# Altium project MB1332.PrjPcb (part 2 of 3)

## Sheet SDcard.SchDoc: SD Card
size A4; Date: Not used; ApprovedBy: Not used; CheckedBy: Not used; Author: Not used; CompanyName: STMicroelectronics; DrawnBy: Not used; Engineer: Not used; Organization: Not used; Address1: Not used; Address2: Not used; Address3: Not used; Address4: Not used; DocumentNumber: Not used; Revision: Not used; SheetNumber: 7; SheetTotal: 17

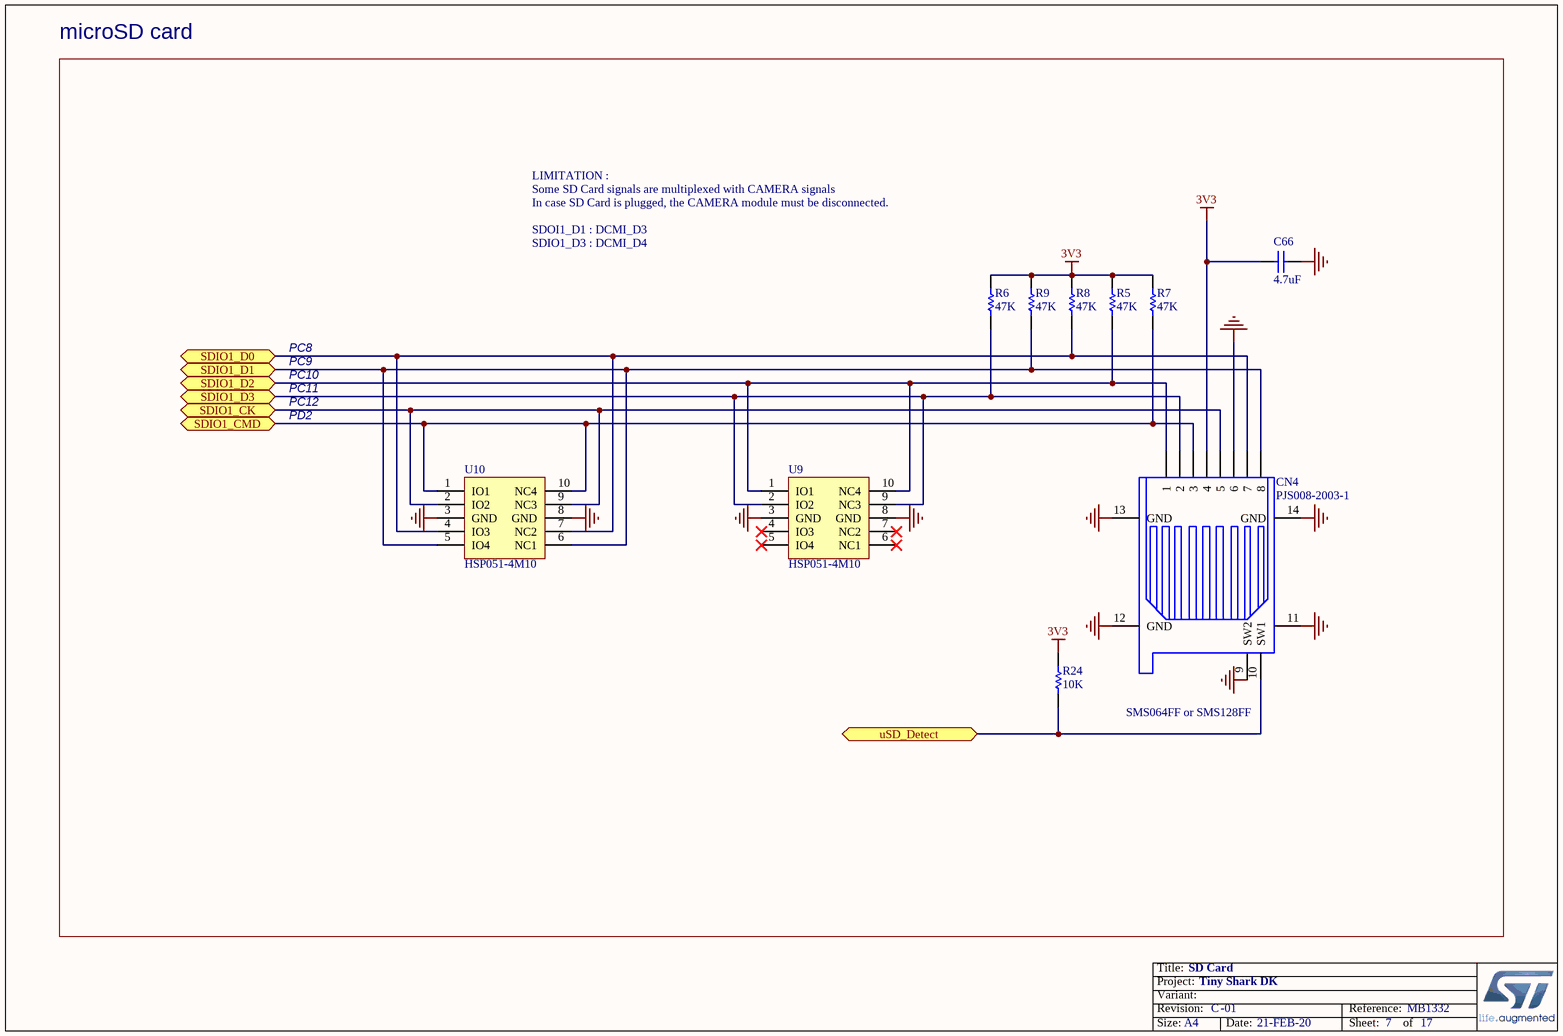
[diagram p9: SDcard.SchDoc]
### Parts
C66  value 4.7uF  [C0603_H0P8]  (hidden comment: Capacitor)
CN4  value PJS008-2003-1  [CON_MICROSD_YAMAICHI_PJS008-2003-1]  (hidden comment: microSD-PJS008-2003)
R5  value 47K  [R0402]  (hidden comment: Resistor)
R6  value 47K  [R0402]  (hidden comment: Resistor)
R7  value 47K  [R0402]  (hidden comment: Resistor)
R8  value 47K  [R0402]  (hidden comment: Resistor)
R9  value 47K  [R0402]  (hidden comment: Resistor)
R24  value 10K  [R0603]  (hidden comment: Resistor)
U9  HSP051-4M10  [ESD_UQFN-10L_2P5X1_P050]
U10  HSP051-4M10  [ESD_UQFN-10L_2P5X1_P050]

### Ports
SDIO1_CK, SDIO1_CMD, SDIO1_D0, SDIO1_D1, SDIO1_D2, SDIO1_D3, uSD_Detect

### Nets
3V3: C66.1 CN4.4 R5.2 R6.2 R7.2 R8.2 R9.2 R24.2
GND: C66.2 CN4.6 CN4.9(SW2) CN4.11(GND) CN4.12(GND) CN4.13(GND) CN4.14(GND) U9.3(GND) U9.8(GND) U10.3(GND) U10.8(GND)
DCMI_D3: CN4.8 R9.1 U10.5(IO4) U10.6(NC1) ; port SDIO1_D1
DCMI_D4: CN4.2 R6.1 U9.2(IO2) U9.9(NC3) ; port SDIO1_D3
SDIO1_CK: CN4.5 U10.2(IO2) U10.9(NC3) ; port SDIO1_CK
SDIO1_CMD: CN4.3 R7.1 U10.1(IO1) U10.10(NC4) ; port SDIO1_CMD
SDIO1_D0: CN4.7 R8.1 U10.4(IO3) U10.7(NC2) ; port SDIO1_D0
SDIO1_D2: CN4.1 R5.1 U9.1(IO1) U9.10(NC4) ; port SDIO1_D2
uSD_Detect: CN4.10(SW1) R24.1 ; port uSD_Detect

Not connected (* = marked no-connect by the designer): U9 4(IO3)* 5(IO4)* 6(NC1)* 7(NC2)*

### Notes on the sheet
- microSD card
- LIMITATION :
  Some SD Card signals are multiplexed with CAMERA signals
  In case SD Card is plugged, the CAMERA module must be disconnected.
  SDOI1_D1 : DCMI_D3
  SDIO1_D3 : DCMI_D4
- PC8
- PC9
- PC10
- PC11
- PD2
- PC12
- SMS064FF or SMS128FF

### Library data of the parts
C66 = MCD-01721: Capacitor, 4.7uF, 10V, X5R, 10%, 0603, T=0.8mm; Manufacturer_Part_Number: CC0603KRX5R6BB475; Manufacturer: YAGEO; Provided_By: SUBCO
CN4 = MCD-00023: MicroSD Card Conn, Reversed-Type, Mnt Push-Push, Positionning holes; Manufacturer: YAMAICHI; Part_Type: Connector; Provided_By: SUBCO
R5-R9 = MCD-00063: Resistor,47K,0402,1%,1/16W; Manufacturer_Part_Number: RC0402FR-0747KL; Manufacturer: YAGEO; Provided_By: SUBCO
R24 = MCD-00220: Resistor,10K,0603,1%,1/10W; Manufacturer_Part_Number: RC0603FR-0710KL; Manufacturer: YAGEO; Provided_By: SUBCO
U9 U10 = MCD-00667: 4-line ESD protection for high speed lines; Part_Type: Diode; Manufacturer: STMICROELECTRONICS; BMS_Part_Number: 9179041; Provided_By: SUBCO with ST control

## Sheet USB_OTG_HS_externalPHY.SchDoc: USB OTG HS with external PHY
size A3; Date: Not used; ApprovedBy: Not used; CheckedBy: Not used; Author: Not used; CompanyName: STMicroelectronics; DrawnBy: Not used; Engineer: Not used; Organization: Not used; Address1: Not used; Address2: Not used; Address3: Not used; Address4: Not used; DocumentNumber: Not used; Revision: Not used; SheetNumber: 4; SheetTotal: 17

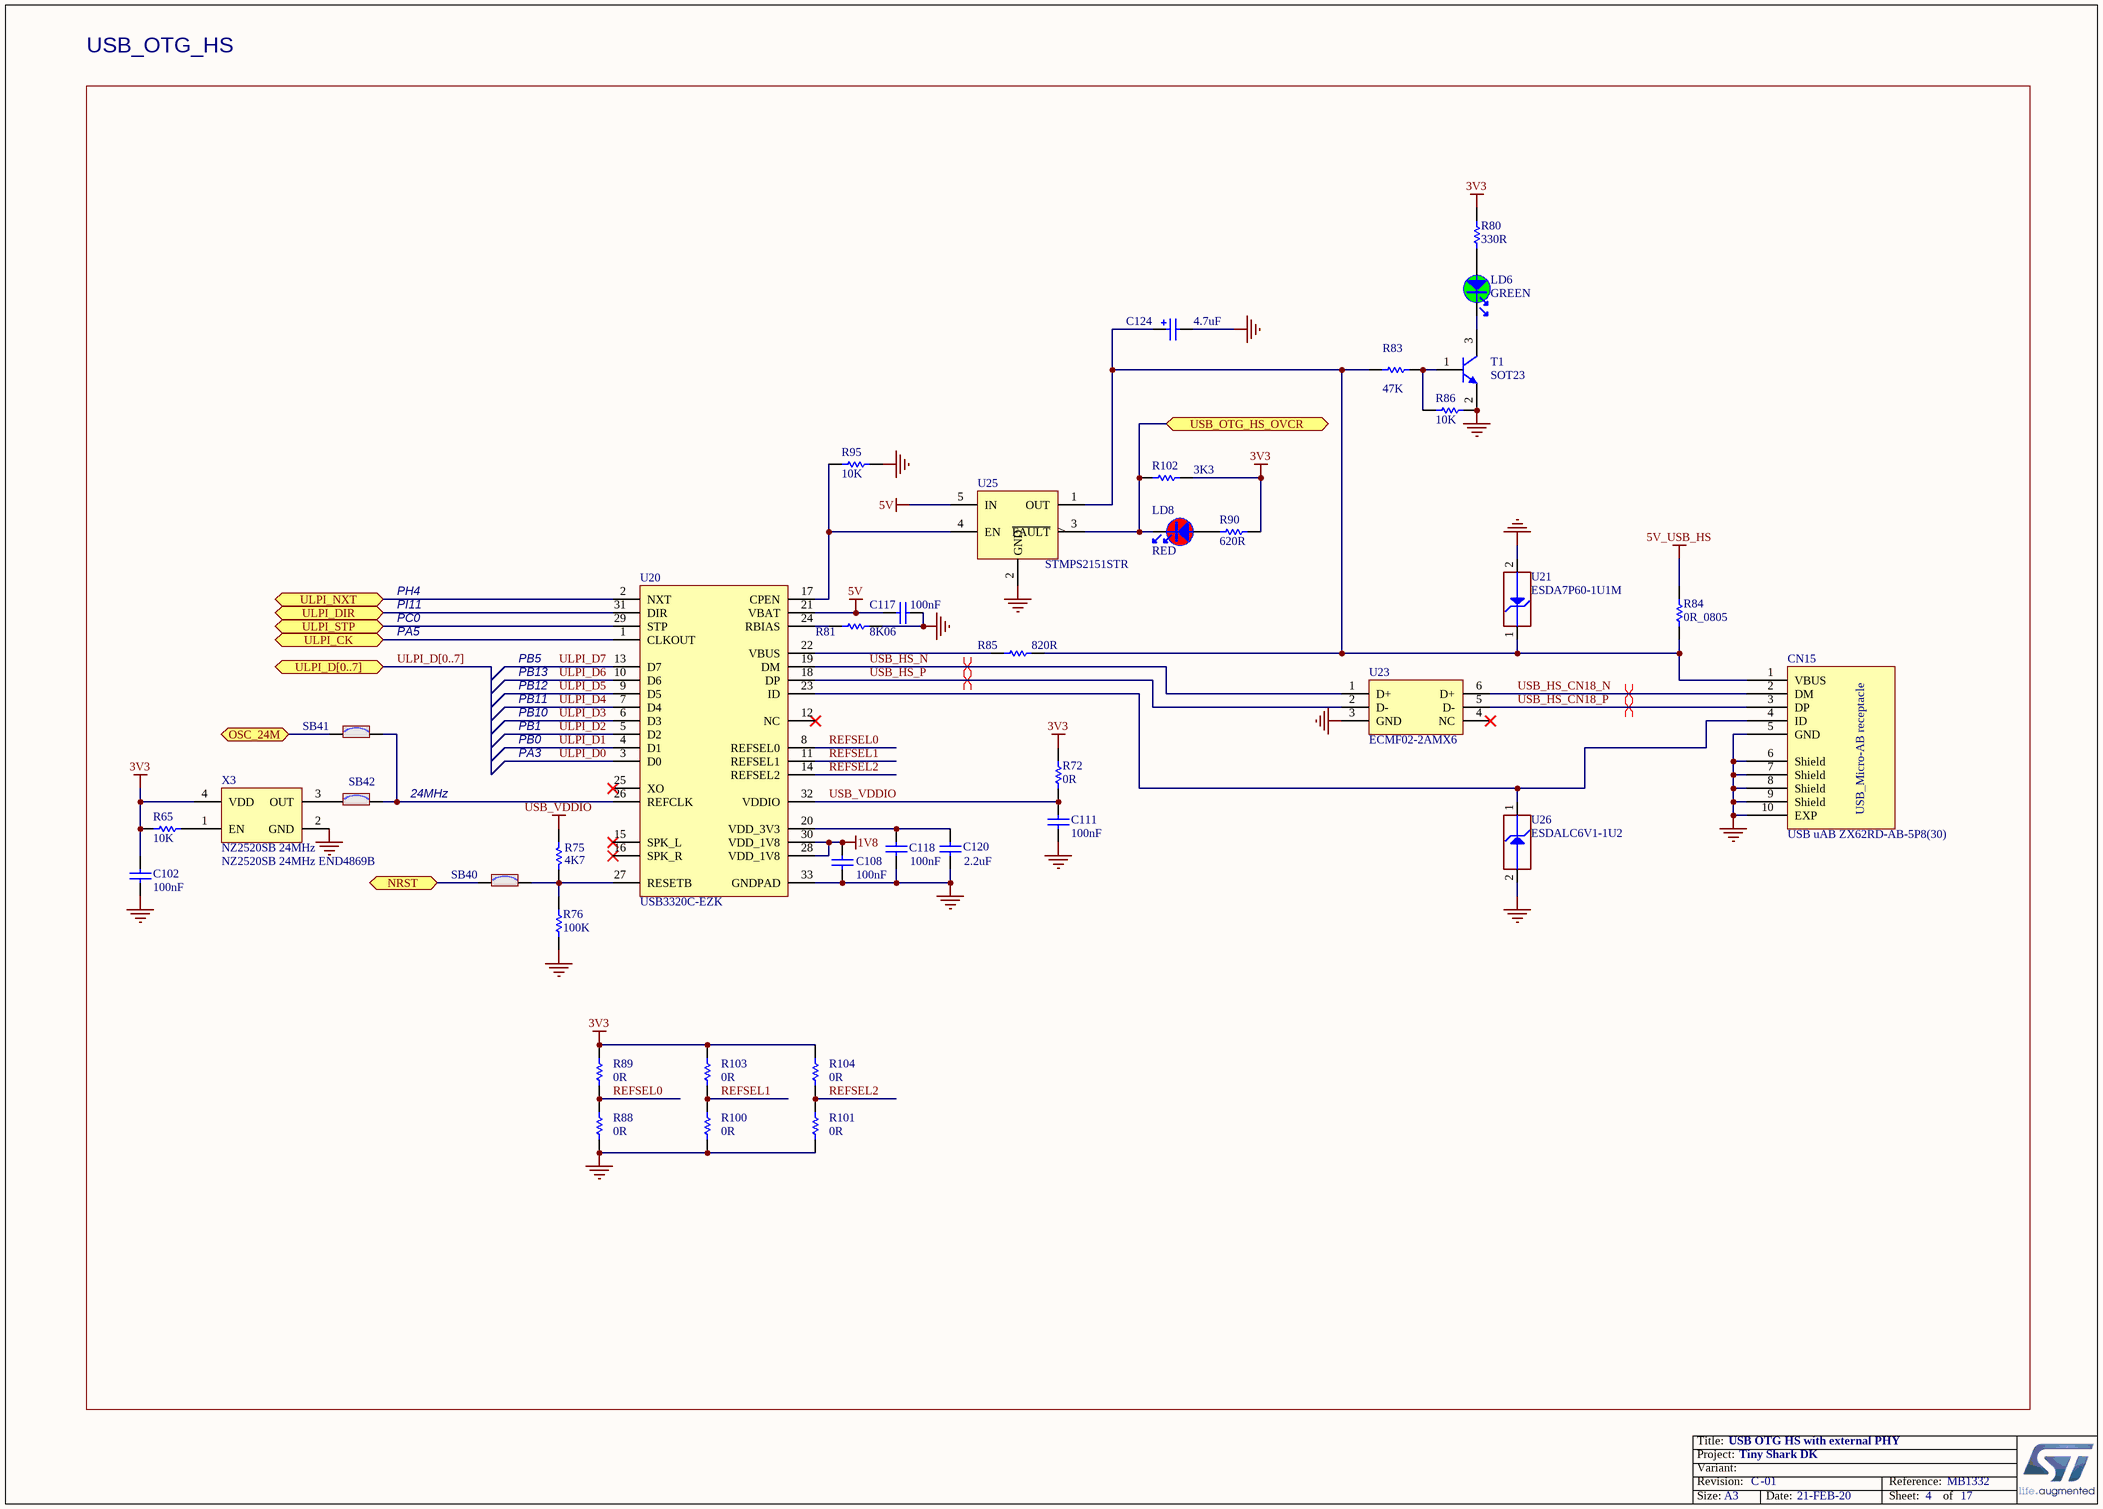
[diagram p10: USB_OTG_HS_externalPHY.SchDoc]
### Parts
C102  value 100nF  [C0402]  (hidden comment: Capacitor)
C108  value 100nF  [C0402]  (hidden comment: Capacitor)
C111  value 100nF  [C0402]  (hidden comment: Capacitor)
C117  value 100nF  [C0402]  (hidden comment: Capacitor)
C118  value 100nF  [C0402]  (hidden comment: Capacitor)
C120  value 2.2uF  [C0603]  (hidden comment: Capacitor)
C124  value 4.7uF  [CPOL_TAJ-A_1206_H180]  (hidden comment: Cap_POL_TANA)
CN15  value USB uAB ZX62RD-AB-5P8(30)  [CON_USBMICROAB_MOLEX_47590-0001_H3]  (hidden comment: USB_uAB_47590.0001)
LD6  value GREEN  [LED_0603_OSRAM_LG-Q396-PS-35_GREEN_1A2K_H0P4]  (hidden comment: LED_green)
LD8  value RED  [LED_0603_VISHAY_VLMS1300-GS08_RED_1A2K_H0P8]  (hidden comment: LED_red)
R65  value 10K  [R0402]  (hidden comment: Resistor)
R72  value 0R  [R0603]  (hidden comment: Resistor)
R75  value 4K7  [R0402]  (hidden comment: Resistor)
R76  value 100K  [R0402]  (hidden comment: Resistor)
R80  value 330R  [R0603]  (hidden comment: Resistor)
R81  value 8K06  [R0603]  (hidden comment: Resistor)
R83  value 47K  [R0402]  (hidden comment: Resistor)
R84  value 0R_0805  [R0805]  (hidden comment: Resistor)
R85  value 820R  [R0603]  (hidden comment: Resistor)
R86  value 10K  [R0402]  (hidden comment: Resistor)
R88  value 0R  [R0603]  (hidden comment: Resistor)
R89  value 0R  [R0603]  (hidden comment: Resistor)
R90  value 620R  [R0603]  (hidden comment: Resistor)
R95  value 10K  [R0402]  (hidden comment: Resistor)
R100  value 0R  [R0603]  (hidden comment: Resistor)
R101  value 0R  [R0603]  (hidden comment: Resistor)
R102  value 3K3  [R0402]  (hidden comment: Resistor)
R103  value 0R  [R0603]  (hidden comment: Resistor)
R104  value 0R  [R0603]  (hidden comment: Resistor)
SB40  SB_ON  [SOLDER-BRIDGE_R0603-0R]  (value not drawn)
SB41  SB_ON  [SOLDER-BRIDGE_R0603-0R]  (value not drawn)
SB42  SB_ON  [SOLDER-BRIDGE_R0603-0R]  (value not drawn)
T1  value SOT23  [NPN_SOT23]  (hidden comment: 9013-SOT23)
U20  USB3320C-EZK  [ICC_QFN32-EPAD_5X5_P050]
U21  value ESDA7P60-1U1M  [ESD_QFN2_1P6X1_P125]  (hidden comment: ESD-TRANSIL)
U23  ECMF02-2AMX6  [ESD_QFN-6L_1P7X1P5_P050]
U25  STMPS2151STR  [MOS_SOT23-5L]
U26  value ESDALC6V1-1U2  [ESD_ST0201]  (hidden comment: ESD-TRANSIL)
X3  value NZ2520SB 24MHz  [OSC_NDK_NZ2520SB_4P]  (hidden comment: OSCILLATOR_4_PINS)

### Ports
NRST, OSC_24M, ULPI_CK, ULPI_D[0..7], ULPI_DIR, ULPI_NXT, ULPI_STP, USB_OTG_HS_OVCR

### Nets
1V8: C108.1 U20.28(VDD_1V8) U20.30(VDD_1V8)
3V3: C102.2 R65.1 R72.1 R80.2 R89.2 R90.2 R102.2 R103.2 R104.2 X3.4(VDD)
5V: C117.1 U20.21(VBAT) U25.5(IN)
5V_USB_HS: R84.2
GND: C102.1 C108.2 C111.2 C117.2 C118.2 C120.1 C124.2 CN15.5(GND) CN15.6(Shield) CN15.7(Shield) CN15.8(Shield) CN15.9(Shield) CN15.10(EXP) R76.1 R81.2 R86.2 R88.1 R95.2 R100.1 R101.1 T1.2(E) U20.33(GNDPAD) U21.2(GND) U23.3(GND) U25.2(GND) U26.2(GND) X3.2(GND)
USB_VDDIO: C111.1 R72.2 R75.2 U20.32(VDDIO)
OSC_24M: SB41.2 ; port OSC_24M
REFSEL0: R88.2 R89.1 U20.8(REFSEL0)
REFSEL1: R100.2 R103.1 U20.11(REFSEL1)
REFSEL2: R101.2 R104.1 U20.14(REFSEL2)
T_NRST: SB40.2 ; port NRST
ULPI_CK: U20.1(CLKOUT) ; port ULPI_CK
ULPI_D0: U20.3(D0)
ULPI_D1: U20.4(D1)
ULPI_D2: U20.5(D2)
ULPI_D3: U20.6(D3)
ULPI_D4: U20.7(D4)
ULPI_D5: U20.9(D5)
ULPI_D6: U20.10(D6)
ULPI_D7: U20.13(D7)
ULPI_DIR: U20.31(DIR) ; port ULPI_DIR
ULPI_NXT: U20.2(NXT) ; port ULPI_NXT
ULPI_STP: U20.29(STP) ; port ULPI_STP
USB_HS_CN18_N: CN15.2(DM) U23.6(D+)
USB_HS_CN18_P: CN15.3(DP) U23.5(D-)
USB_HS_N: U20.19(DM) U23.1(D+)
USB_HS_P: U20.18(DP) U23.2(D-)
USB_OTG_HS_OVCR: LD8.2 R102.1 U25.3(~{FAULT}) ; port USB_OTG_HS_OVCR
NetC118_1: C118.1 C120.2 U20.20(VDD_3V3)
NetC124_1: C124.1 CN15.1(VBUS) R83.1 R84.1 R85.2 U21.1(IO1) U25.1(OUT)
NetCN15_4: CN15.4(ID) U20.23(ID) U26.1(IO1)
NetLD6_1: LD6.1 R80.1
NetLD6_2: LD6.2 T1.3(C)
NetLD8_1: LD8.1 R90.1
NetR65_2: R65.2 X3.1(EN)
NetR75_1: R75.1 R76.2 SB40.1 U20.27(RESETB)
NetR81_1: R81.1 U20.24(RBIAS)
NetR83_2: R83.2 R86.1 T1.1(B)
NetR85_1: R85.1 U20.22(VBUS)
NetR95_1: R95.1 U20.17(CPEN) U25.4(EN)
NetSB41_1: SB41.1 SB42.1 U20.26(REFCLK)
NetSB42_2: SB42.2 X3.3(OUT)

Not connected (* = marked no-connect by the designer): U20 12(NC)* 15(SPK_L)* 16(SPK_R)* 25(XO)*; U23 4(NC)*

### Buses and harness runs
bus ULPI_D[0..7] = port ULPI_D[0..7]

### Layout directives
differential pair: USB_HS_CN18_N, USB_HS_CN18_P, USB_HS_N, USB_HS_P

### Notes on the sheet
- USB_OTG_HS
- PH4
- PI11
- PC0
- PA5
- PB10
- PB11
- PB12
- PB13
- PB5
- PA3
- PB0
- PB1
- (near SB42) 24MHz
- (near X3) NZ2520SB 24MHz END4869B

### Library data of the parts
C102 C108 C111 C117 C118 = MCD-00006: Capacitor, MLCC, 100nF, 16V, X7R, 10%, 0402, T=0.5mm; Manufacturer_Part_Number: CC0402KRX7R7BB104; Manufacturer: YAGEO; Alternate_Manufacturer_Part_Number: GCM155R71C104KA55D; Alternate_Manufacturer: MURATA; Provided_By: SUBCO
C120 = MCD-00012: Capacitor, MLCC, 2.2uF, 10V, X5R, 10%, 0603, T=0,8mm; Manufacturer_Part_Number: CC0603KRX5R6BB225; Manufacturer: YAGEO; Alternate_Manufacturer_Part_Number: C0603C225K8PACTU; Alternate_Manufacturer: KEMET; Provided_By: SUBCO
C124 = MCD-00007: Capacitor, Tantalum, 4.7uF, 16V, 10%, TypeA; Manufacturer_Part_Number: TAJA475K016R; Manufacturer: AVX; Provided_By: SUBCO
CN15 = MCD-00661: USB-MICRO-AB Receptacle, RA, SMT + DIP, Standard, Top Mount, USB certified (symbol & footprint compatible with MCD-00022); Part_Type: Connector; Manufacturer_Part_Number: ZX62RD-AB-5P8(30); Manufacturer: HIROSE; Provided_By: SUBCO
LD6 = MCD-00588: LED Green, 0603 SMD, Forward Voltage Typ=2V, Max=2.5V; Part_Type: Display; Manufacturer_Part_Number: LG Q396-PS-35; Manufacturer: OSRAM OPTO SEMICONDUCTORS; Alternate_Manufacturer_Part_Number: VLMTG1300-GS08; Alternate_Manufacturer: VISHAY SEMICONDUCTOR OPTO DIVISION; Provided_By: SUBCO
LD8 = MCD-00587: LED Red, 0603 SMD, 2V Forward Voltage; Manufacturer_Part_Number: VLMS1300-GS08; Manufacturer: VISHAY; Alternate_Manufacturer_Part_Number: LS Q976-NR-1; Alternate_Manufacturer: OSRAM OPTO SEMICONDUCTORS; Part_Type: Display; Provided_By: SUBCO
R65 R86 R95 = MCD-00053: Resistor,10K,0402,1%,1/16W; Manufacturer_Part_Number: RC0402FR-0710KL; Manufacturer: YAGEO; Provided_By: SUBCO
R72 R88 R89 R100 R101 R103 R104 = MCD-00056: Resistor,0R,0603,5%,1/10W; Manufacturer_Part_Number: RC0603JR-070RL; Manufacturer: YAGEO; Provided_By: SUBCO
R75 = MCD-00065: Resistor,4K7,0402,1%,1/16W; Manufacturer_Part_Number: RC0402FR-074K7L; Manufacturer: YAGEO; Alternate_Manufacturer_Part_Number: RT0402FRE074K7L; Provided_By: SUBCO
R76 = MCD-00059: Resistor,100K,0402,1%,1/16W; Manufacturer_Part_Number: RC0402FR-07100KL; Manufacturer: YAGEO; Alternate_Manufacturer_Part_Number: RT0402FRE07100KL; Provided_By: SUBCO
R80 = MCD-00197: Resistor,330R,0603,1%,1/10W; Manufacturer_Part_Number: RC0603FR-07330RL; Manufacturer: YAGEO; BMS_Part_Number: 9129729; Provided_By: SUBCO
R81 = MCD-00570: Resistor,8K06,0603,1%,1/10W; Manufacturer_Part_Number: RC0603FR-078K06L; Manufacturer: YAGEO; Provided_By: SUBCO
R83 = MCD-00063: as R5 on sheet SDcard
R84 = MCD-00179: Resistor,0R,0805,5%; Manufacturer_Part_Number: RC0805JR-070RL; Manufacturer: YAGEO; Provided_By: SUBCO
R85 = MCD-00528: Resistor,820R,0603,1%,1/10W; Manufacturer_Part_Number: RC0603FR-07820RL; Manufacturer: YAGEO; BMS_Part_Number: 9129759; Provided_By: SUBCO
R90 = MCD-00500: Resistor,620R,0603,1%,1/10W; Manufacturer_Part_Number: RC0603FR-07620RL; Manufacturer: YAGEO; Provided_By: SUBCO
R102 = MCD-00184: Resistor,3K3,0402,1%,1/16W; Manufacturer_Part_Number: RC0402FR-073K3L; Manufacturer: YAGEO; Provided_By: SUBCO
SB40-SB42 = MCD-00071: Solder Bridge ON; Part_Type: Mechanical; Manufacturer_Part_Number: RC0603JR-070RL; Manufacturer: YAGEO; Provided_By: SUBCO
T1 = MCD-00073: NPN Bipolar Transistor; Manufacturer_Part_Number: BSR14; Manufacturer: ON SEMICONDUCTOR; Part_Type: IC; Alternate_Manufacturer_Part_Number: MMBT2222ALT1G / MMBT2222ALT3G; Provided_By: SUBCO
U20 = MCD-00569: USB3320C,  Hi-Speed USB Host, Device or OTG PHY with ULPI Low Pin Interface; Manufacturer_Part_Number: USB3320C-EZK-TR; Manufacturer: MICROCHIP; Part_Type: IC; Provided_By: SUBCO
U21 = MCD-00251: High power transient voltage suppressor, 7V breakdown; Part_Type: Diode; Manufacturer: STMICROELECTRONICS; BMS_Part_Number: 9179042; Provided_By: SUBCO with ST control
U23 = MCD-00649: Common mode filter with ESD protection for USB 2.0 interface; Part_Type: Diode; Manufacturer: STMICROELECTRONICS; BMS_Part_Number: 9151138; Provided_By: SUBCO with ST control
U25 = MCD-00159: 500mA, Enhanced single channel power switches with active high enable pin; Manufacturer: STMICROELECTRONICS; Part_Type: IC; Alternate_Manufacturer_Part_Number: TPS2051C; Alternate_Manufacturer: TEXAS INSTRUMENTS; BMS_Part_Number: 9159009; Provided_By: SUBCO with ST control
U26 = MCD-00170: ESD protection 6V1; Part_Type: Diode; Manufacturer: STMICROELECTRONICS; BMS_Part_Number: 9151132; Provided_By: SUBCO with ST control
X3 = MCD-01014: Oscillator 24Mhz, +-50ppm, Vcc:3.3V typ, square wave: [0.1Vcc;0.9Vcc], Enable pin; Part_Type: Crystal_Osc; Manufacturer_Part_Number: NZ2520SB 24MHz END4869A; Manufacturer: NDK; Alternate_Manufacturer_Part_Number: AVX Corp/Kyocera Corp; Alternate_Manufacturer: KC2520B24.0000C10E00; BMS_Part_Number: 9157032; Provided_By: SUBCO

## Sheet MCU.SchDoc: MCU STM32H7B3LIH6QU
size A3; Date: Not used; ApprovedBy: Not used; CheckedBy: Not used; Author: Not used; CompanyName: STMicroelectronics; DrawnBy: Not used; Engineer: Not used; Organization: Not used; Address1: Not used; Address2: Not used; Address3: Not used; Address4: Not used; DocumentNumber: Not used; Revision: Not used; SheetNumber: 3; SheetTotal: 17

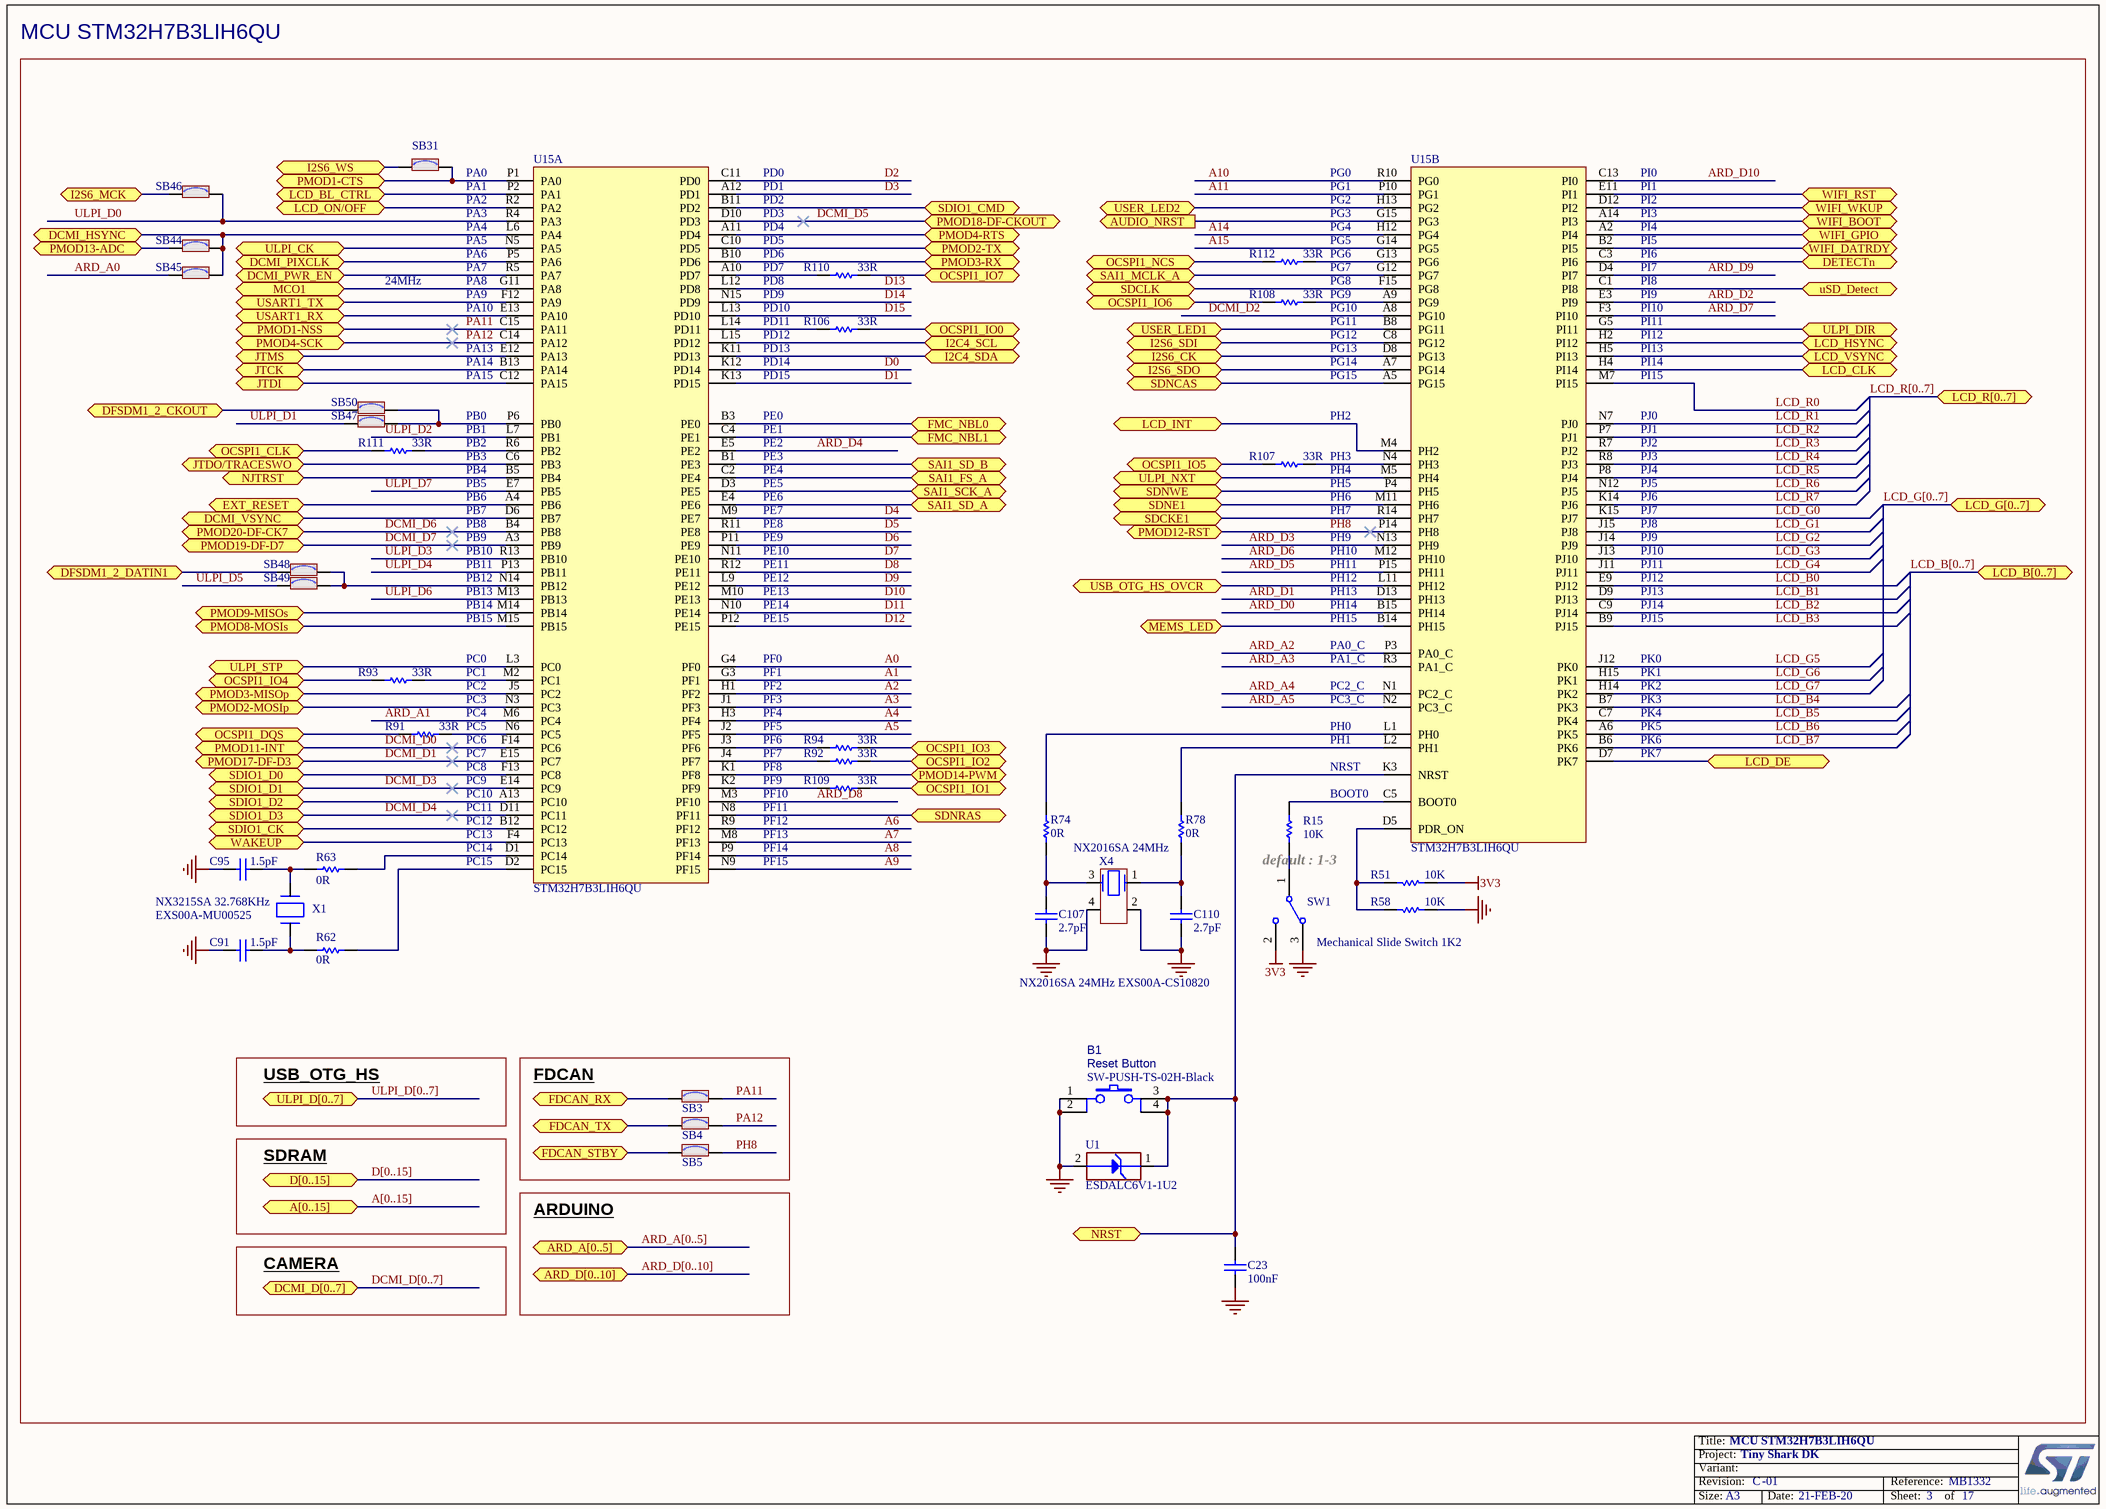
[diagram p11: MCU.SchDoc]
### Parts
B1  SW-PUSH-TS-02H-Black  [SWI_JIUBABA_C-TS-02H-2-5-K-V-T_R_BLACK]
C23  value 100nF  [C0402]  (hidden comment: Capacitor)
C91  value 1.5pF  [C0402]  (hidden comment: Capacitor)
C95  value 1.5pF  [C0402]  (hidden comment: Capacitor)
C107  value 2.7pF  [C0402]  (hidden comment: Capacitor)
C110  value 2.7pF  [C0402]  (hidden comment: Capacitor)
R15  value 10K  [R0402]  (hidden comment: Resistor)
R51  value 10K  [R0402]  (hidden comment: Resistor)
R58  value 10K  [R0402]  (hidden comment: Resistor)
R62  value 0R  [R0402]  (hidden comment: Resistor)
R63  value 0R  [R0402]  (hidden comment: Resistor)
R74  value 0R  [R0402]  (hidden comment: Resistor)
R78  value 0R  [R0402]  (hidden comment: Resistor)
R91  value 33R  [R0402]  (hidden comment: Resistor)
R92  value 33R  [R0402]  (hidden comment: Resistor)
R93  value 33R  [R0402]  (hidden comment: Resistor)
R94  value 33R  [R0402]  (hidden comment: Resistor)
R106  value 33R  [R0402]  (hidden comment: Resistor)
R107  value 33R  [R0402]  (hidden comment: Resistor)
R108  value 33R  [R0402]  (hidden comment: Resistor)
R109  value 33R  [R0402]  (hidden comment: Resistor)
R110  value 33R  [R0402]  (hidden comment: Resistor)
R111  value 33R  [R0402]  (hidden comment: Resistor)
R112  value 33R  [R0402]  (hidden comment: Resistor)
SB3  SB_ON  [SOLDER-BRIDGE_R0603-0R]  (value not drawn)
SB4  SB_ON  [SOLDER-BRIDGE_R0603-0R]  (value not drawn)
SB5  SB_ON  [SOLDER-BRIDGE_R0603-0R]  (value not drawn)
SB31  SB_ON  [SOLDER-BRIDGE_R0603-0R]  (value not drawn)
SB44  SB_ON  [SOLDER-BRIDGE_R0603-0R]  (value not drawn)
SB45  SB_ON  [SOLDER-BRIDGE_R0603-0R]  (value not drawn)
SB46  SB_ON  [SOLDER-BRIDGE_R0603-0R]  (value not drawn)
SB47  SB_ON  [SOLDER-BRIDGE_R0603-0R]  (value not drawn)
SB48  SB_ON  [SOLDER-BRIDGE_R0603-0R]  (value not drawn)
SB49  SB_ON  [SOLDER-BRIDGE_R0603-0R]  (value not drawn)
SB50  SB_ON  [SOLDER-BRIDGE_R0603-0R]  (value not drawn)
SW1  value Mechanical Slide Switch 1K2  [SWI_EAO_09-03290-01_EXTENDED_STRAIGHT_BLACK]  (hidden comment: SW_MECA_1K2)
U1  value ESDALC6V1-1U2  [ESD_ST0201]  (hidden comment: ESD-TRANSIL)
U15  value STM32H7B3LIH6QU  [ICC_TFBGA225_13X13_STM32H7B3NIH6Q_P080]  (hidden comment: STM32H7B3NIH6Q)  (parts A,B of 3)
X1  value NX3215SA 32.768KHz  [CRY_NX3215SA_2P]  (hidden comment: XTAL_2_PINS)
X4  value NX2016SA 24MHz  Manufacturer_Part_Number: NX2016SA 24MHz EXS00A-CS10820  [CRY_NX2016SA_4P]  (hidden comment: XTAL_4_PINS)

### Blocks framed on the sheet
FDCAN: SB3-SB5

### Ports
A[0..15], ARD_A[0..5], ARD_D[0..10], AUDIO_NRST (out), D[0..15], DCMI_D[0..7], DCMI_HSYNC, DCMI_PIXCLK, DCMI_PWR_EN, DCMI_VSYNC, DETECTn, DFSDM1_2_CKOUT, DFSDM1_2_DATIN1, EXT_RESET, FDCAN_RX, FDCAN_STBY, FDCAN_TX, FMC_NBL0, FMC_NBL1, I2C4_SCL, I2C4_SDA, I2S6_CK, I2S6_MCK (bidir), I2S6_SDI, I2S6_SDO, I2S6_WS, JTCK, JTDI, JTDO/TRACESWO, JTMS, LCD_B[0..7], LCD_BL_CTRL, LCD_CLK, LCD_DE, LCD_G[0..7], LCD_HSYNC, LCD_INT, LCD_ON/OFF, LCD_R[0..7], LCD_VSYNC, MCO1, MEMS_LED, NJTRST, NRST, OCSPI1_CLK, OCSPI1_DQS, OCSPI1_IO0, OCSPI1_IO1, OCSPI1_IO2, OCSPI1_IO3, OCSPI1_IO4, OCSPI1_IO5, OCSPI1_IO6, OCSPI1_IO7, OCSPI1_NCS, PMOD1-CTS, PMOD1-NSS, PMOD2-MOSIp, PMOD2-TX, PMOD3-MISOp, PMOD3-RX, PMOD4-RTS, PMOD4-SCK, PMOD8-MOSIs, PMOD9-MISOs, PMOD11-INT, PMOD12-RST, PMOD13-ADC, PMOD14-PWM, PMOD17-DF-D3, PMOD18-DF-CKOUT, PMOD19-DF-D7, PMOD20-DF-CK7, SAI1_FS_A, SAI1_MCLK_A, SAI1_SCK_A, SAI1_SD_A, SAI1_SD_B, SDCKE1, SDCLK, SDIO1_CK, SDIO1_CMD, SDIO1_D0, SDIO1_D1, SDIO1_D2, SDIO1_D3, SDNCAS, SDNE1, SDNRAS, SDNWE, ULPI_CK, ULPI_D[0..7], ULPI_DIR, ULPI_NXT, ULPI_STP, USART1_RX, USART1_TX, USB_OTG_HS_OVCR, uSD_Detect, USER_LED1, USER_LED2, WAKEUP, WIFI_BOOT, WIFI_DATRDY, WIFI_GPIO, WIFI_RST, WIFI_WKUP

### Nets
3V3: R51.1 SW1.2
GND: B1.1 B1.2 C23.1 C91.1 C95.1 C107.1 C110.1 R58.1 SW1.3 U1.2(GND) X4.2 X4.4
2_CTS: SB31.1 U15.P1(PA0) ; port PMOD1-CTS
2_RTS: U15.A11(PD4) ; port PMOD4-RTS
2_RX: U15.B10(PD6) ; port PMOD3-RX
2_TX: U15.C10(PD5) ; port PMOD2-TX
A0: U15.G4(PF0)
A1: U15.G3(PF1)
A2: U15.H1(PF2)
A3: U15.J1(PF3)
A4: U15.H3(PF4)
A5: U15.J2(PF5)
A6: U15.R9(PF12)
A7: U15.M8(PF13)
A8: U15.P9(PF14)
A9: U15.N9(PF15)
A10: U15.R10(PG0)
A11: U15.P10(PG1)
A14: U15.H12(PG4)
A15: U15.G14(PG5)
ARD_A0: SB45.2
ARD_A1: U15.M6(PC4)
ARD_A2: U15.P3(PA0_C)
ARD_A3: U15.R3(PA1_C)
ARD_A4: U15.N1(PC2_C)
ARD_A5: U15.N2(PC3_C)
ARD_D0: U15.B15(PH14)
ARD_D1: U15.D13(PH13)
ARD_D2: U15.E3(PI9)
ARD_D3: U15.N13(PH9)
ARD_D4: U15.E5(PE2)
ARD_D5: U15.P15(PH11)
ARD_D6: U15.M12(PH10)
ARD_D7: U15.F3(PI10)
ARD_D8: U15.M3(PF10)
ARD_D9: U15.D4(PI7)
ARD_D10: U15.C13(PI0)
AUDIO_NRST: U15.G15(PG3) ; port AUDIO_NRST
CKOUT: SB50.2 ; port DFSDM1_2_CKOUT
D0: U15.K12(PD14)
D1: U15.K13(PD15)
D2: U15.C11(PD0)
D3: U15.A12(PD1)
D4: U15.M9(PE7)
D5: U15.R11(PE8)
D6: U15.P11(PE9)
D7: U15.N11(PE10)
D8: U15.R12(PE11)
D9: U15.L9(PE12)
D10: U15.M10(PE13)
D11: U15.N10(PE14)
D12: U15.P12(PE15)
D13: U15.L12(PD8)
D14: U15.N15(PD9)
D15: U15.L13(PD10)
DCMI_D0: U15.F14(PC6) ; port PMOD11-INT
DCMI_D1: U15.E15(PC7) ; port PMOD17-DF-D3
DCMI_D2: U15.A8(PG10)
DCMI_D3: U15.E14(PC9) ; port SDIO1_D1
DCMI_D4: U15.D11(PC11) ; port SDIO1_D3
DCMI_D5: U15.D10(PD3) ; port PMOD18-DF-CKOUT
DCMI_D6: U15.B4(PB8) ; port PMOD20-DF-CK7
DCMI_D7: U15.A3(PB9) ; port PMOD19-DF-D7
DCMI_HSYNC: SB44.1 SB45.1 U15.L6(PA4) ; port DCMI_HSYNC
DCMI_PIXCLK: U15.P5(PA6) ; port DCMI_PIXCLK
DCMI_PWR_EN: U15.R5(PA7) ; port DCMI_PWR_EN
DCMI_VSYNC: U15.D6(PB7) ; port DCMI_VSYNC
DETECTn: U15.C3(PI6) ; port DETECTn
DFSDM1_2_DATIN1: SB48.2 ; port DFSDM1_2_DATIN1
EXT_RESET: U15.A4(PB6) ; port EXT_RESET
FDCAN_RX: SB3.1 ; port FDCAN_RX
FDCAN_STBY: SB5.1 ; port FDCAN_STBY
FDCAN_TX: SB4.1 ; port FDCAN_TX
FMC_NBL0: U15.B3(PE0) ; port FMC_NBL0
FMC_NBL1: U15.C4(PE1) ; port FMC_NBL1
I2C4_SCL: U15.L15(PD12) ; port I2C4_SCL
I2C4_SDA: U15.K11(PD13) ; port I2C4_SDA
I2S6_CK: U15.D8(PG13) ; port I2S6_CK
I2S6_MCK: SB46.2 ; port I2S6_MCK
I2S6_SDI: U15.C8(PG12) ; port I2S6_SDI
I2S6_SDO: U15.A7(PG14) ; port I2S6_SDO
I2S6_WS: SB31.2 ; port I2S6_WS
JTDI: U15.C12(PA15) ; port JTDI
LCD_B0: U15.E9(PJ12)
LCD_B1: U15.D9(PJ13)
LCD_B2: U15.C9(PJ14)
LCD_B3: U15.B9(PJ15)
LCD_B4: U15.B7(PK3)
LCD_B5: U15.C7(PK4)
LCD_B6: U15.A6(PK5)
LCD_B7: U15.B6(PK6)
LCD_BL_CTRL: U15.P2(PA1) ; port LCD_BL_CTRL
LCD_CLK: U15.H4(PI14) ; port LCD_CLK
LCD_DE: U15.D7(PK7) ; port LCD_DE
LCD_G0: U15.K15(PJ7)
LCD_G1: U15.J15(PJ8)
LCD_G2: U15.J14(PJ9)
LCD_G3: U15.J13(PJ10)
LCD_G4: U15.J11(PJ11)
LCD_G5: U15.J12(PK0)
LCD_G6: U15.H15(PK1)
LCD_G7: U15.H14(PK2)
LCD_HSYNC: U15.H2(PI12) ; port LCD_HSYNC
LCD_INT: U15.M4(PH2) ; port LCD_INT
LCD_ON/OFF: U15.R2(PA2) ; port LCD_ON/OFF
LCD_R0: U15.M7(PI15)
LCD_R1: U15.N7(PJ0)
LCD_R2: U15.P7(PJ1)
LCD_R3: U15.R7(PJ2)
LCD_R4: U15.R8(PJ3)
LCD_R5: U15.P8(PJ4)
LCD_R6: U15.N12(PJ5)
LCD_R7: U15.K14(PJ6)
LCD_VSYNC: U15.H5(PI13) ; port LCD_VSYNC
MCO1: U15.G11(PA8) ; port MCO1
MEMS_LED: U15.B14(PH15) ; port MEMS_LED
MISO: U15.J5(PC2) ; port PMOD3-MISOp
MOSI: U15.N3(PC3) ; port PMOD2-MOSIp
NJTRST: U15.B5(PB4) ; port NJTRST
OCSPI1_CLK: R111.1 ; port OCSPI1_CLK
OCSPI1_DQS: R91.1 ; port OCSPI1_DQS
OCSPI1_IO0: R106.2 ; port OCSPI1_IO0
OCSPI1_IO1: R109.2 ; port OCSPI1_IO1
OCSPI1_IO2: R92.2 ; port OCSPI1_IO2
OCSPI1_IO3: R94.2 ; port OCSPI1_IO3
OCSPI1_IO4: R93.1 ; port OCSPI1_IO4
OCSPI1_IO5: R107.1 ; port OCSPI1_IO5
OCSPI1_IO6: R108.1 ; port OCSPI1_IO6
OCSPI1_IO7: R110.2 ; port OCSPI1_IO7
OCSPI1_NCS: R112.1 ; port OCSPI1_NCS
PA11: SB3.2 U15.C15(PA11) ; port PMOD1-NSS  [project net nSS]
PA12: SB4.2 U15.C14(PA12) ; port PMOD4-SCK
PH8: SB5.2 U15.P14(PH8) ; port PMOD12-RST
PMOD8-MOSIs: U15.M15(PB15) ; port PMOD8-MOSIs
PMOD9: U15.M14(PB14) ; port PMOD9-MISOs
PMOD13-ADC: SB44.2 ; port PMOD13-ADC
PMOD14-PWM: U15.K1(PF8) ; port PMOD14-PWM
SAI1_FS_A: U15.C2(PE4) ; port SAI1_FS_A
SAI1_MCLK_A: U15.G12(PG7) ; port SAI1_MCLK_A
SAI1_SCK_A: U15.D3(PE5) ; port SAI1_SCK_A
SAI1_SD_A: U15.E4(PE6) ; port SAI1_SD_A
SAI1_SD_B: U15.B1(PE3) ; port SAI1_SD_B
SDCKE1: U15.R14(PH7) ; port SDCKE1
SDCLK: U15.F15(PG8) ; port SDCLK
SDIO1_CK: U15.B12(PC12) ; port SDIO1_CK
SDIO1_CMD: U15.B11(PD2) ; port SDIO1_CMD
SDIO1_D0: U15.F13(PC8) ; port SDIO1_D0
SDIO1_D2: U15.A13(PC10) ; port SDIO1_D2
SDNCAS: U15.A5(PG15) ; port SDNCAS
SDNE1: U15.M11(PH6) ; port SDNE1
SDNRAS: U15.N8(PF11) ; port SDNRAS
SDNWE: U15.P4(PH5) ; port SDNWE
T_NRST: B1.3 B1.4 C23.2 U1.1(IO1) U15.K3(NRST) ; port NRST
T_SWCLK: U15.B13(PA14) ; port JTCK
T_SWDIO: U15.E12(PA13) ; port JTMS
T_SWO: U15.C6(PB3) ; port JTDO/TRACESWO
ULPI_CK: U15.N5(PA5) ; port ULPI_CK
ULPI_D0: SB46.1 U15.R4(PA3)
ULPI_D1: SB47.2
ULPI_D2: U15.L7(PB1)
ULPI_D3: U15.R13(PB10)
ULPI_D4: U15.P13(PB11)
ULPI_D5: SB49.2
ULPI_D6: U15.M13(PB13)
ULPI_D7: U15.E7(PB5)
ULPI_DIR: U15.G5(PI11) ; port ULPI_DIR
ULPI_NXT: U15.M5(PH4) ; port ULPI_NXT
ULPI_STP: U15.L3(PC0) ; port ULPI_STP
USART1_RX: U15.E13(PA10) ; port USART1_RX
USART1_TX: U15.F12(PA9) ; port USART1_TX
USB_OTG_HS_OVCR: U15.L11(PH12) ; port USB_OTG_HS_OVCR
uSD_Detect: U15.C1(PI8) ; port uSD_Detect
USER_LED1: U15.B8(PG11) ; port USER_LED1
USER_LED2: U15.H13(PG2) ; port USER_LED2
WAKEUP: U15.F4(PC13) ; port WAKEUP
WIFI_BOOT: U15.A14(PI3) ; port WIFI_BOOT
WIFI_DATRDY: U15.B2(PI5) ; port WIFI_DATRDY
WIFI_GPIO: U15.A2(PI4) ; port WIFI_GPIO
WIFI_RST: U15.E11(PI1) ; port WIFI_RST
WIFI_WKUP: U15.D12(PI2) ; port WIFI_WKUP
NetC91_2: C91.2 R62.1 X1.2(X2)
NetC95_2: C95.2 R63.1 X1.1(X1)
NetC107_2: C107.2 R74.1 X4.3
NetC110_2: C110.2 R78.1 X4.1
NetR15_1: R15.1 U15.C5(BOOT0)
NetR15_2: R15.2 SW1.1
NetR51_2: R51.2 R58.2 U15.D5(PDR_ON)
NetR62_2: R62.2 U15.D2(PC15)
NetR63_2: R63.2 U15.D1(PC14)
NetR74_2: R74.2 U15.L1(PH0)
NetR78_2: R78.2 U15.L2(PH1)
NetR91_2: R91.2 U15.N6(PC5)
NetR92_1: R92.1 U15.J4(PF7)
NetR93_2: R93.2 U15.M2(PC1)
NetR94_1: R94.1 U15.J3(PF6)
NetR106_1: R106.1 U15.L14(PD11)
NetR107_2: R107.2 U15.N4(PH3)
NetR108_2: R108.2 U15.A9(PG9)
NetR109_1: R109.1 U15.K2(PF9)
NetR110_1: R110.1 U15.A10(PD7)
NetR111_2: R111.2 U15.R6(PB2)
NetR112_2: R112.2 U15.G13(PG6)
NetSB47_1: SB47.1 SB50.1 U15.P6(PB0)
NetSB48_1: SB48.1 SB49.1 U15.N14(PB12)

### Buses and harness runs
bus A[0..15] = port A[0..15]
bus ARD_A[0..5] = port ARD_A[0..5]
bus ARD_D[0..10] = port ARD_D[0..10]
bus D[0..15] = port D[0..15]
bus DCMI_D[0..7] = port DCMI_D[0..7]
bus LCD_B[0..7] = port LCD_B[0..7]
bus LCD_G[0..7] = port LCD_G[0..7]
bus LCD_R[0..7] = port LCD_R[0..7]
bus ULPI_D[0..7] = port ULPI_D[0..7]

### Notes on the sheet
- MCU STM32H7B3LIH6QU
- (near SB31) PA0
- PD0
- PG0
- PI0
- PA1
- PA2
- PA3
- PA4
- PA5
- PD1
- PD2
- PD3
- PD4
- PD5
- PG1
- PG2
- PG3
- (near R112) PG4
- (near R112) PG5
- PI1
- PI2
- PI3
- PI4
- PI5
- 24MHz
- (near U15) PA6
- (near U15) PA7
- (near U15) PA8
- (near U15) PA9
- (near U15) PA10
- PD6
- PD7
- PD8
- PD9
- PD10
- (near R112) PG6
- PG7
- PG8
- PG9
- (near R108) PG10
- PI6
- PI7
- PI8
- PI9
- PI10
- (near U15) PA13
- (near U15) PA14
- (near U15) PA15
- PD11
- PD12
- PD13
- PD14
- PD15
- (near R108) PG11
- PG12
- PG13
- PG14
- PG15
- PI11
- PI12
- PI13
- PI14
- PI15
- PB0
- PB1
- PB2
- PE0
- PE1
- PE2
- PH2
- PJ0
- PJ1
- PJ2
- PB3
- PB4
- PB5
- PB6
- PB7
- PE3
- PE4
- PE5
- PE6
- PE7
- (near R107) PH3
- (near R107) PH4
- (near R107) PH5
- (near R107) PH6
- PH7
- PJ3
- PJ4
- PJ5
- PJ6
- PJ7
- (near U15) PB8
- (near U15) PB9
- (near U15) PB10
- (near U15) PB11
- (near U15) PB12
- PE8
- PE9
- PE10
- PE11
- PE12
- PH9
- PH10
- PH11
- PH12
- PJ8
- PJ9
- PJ10
- PJ11
- PJ12
- (near U15) PB13
- (near U15) PB14
- (near U15) PB15
- PE13
- PE14
- PE15
- PH13
- PH14
- PH15
- (near U15) PA0_C
- PJ13
- PJ14
- PJ15
- PC0
- PC1
- PC2
- PC3
- PC4
- PF0
- PF1
- PF2
- PF3
- PF4
- (near U15) PA1_C
- (near U15) PC2_C
- (near U15) PC3_C
- PK0
- PK1
- PK2
- PK3
- PK4
- (near R91) PC5
- (near R91) PC6
- PC7
- PC8
- PC9
- PF5
- PF6
- PF7
- PF8
- PF9
- PH0
- PH1
- NRST
- PK5
- PK6
- PK7
- PC10
- (near U15) PC11
- (near U15) PC12
- (near U15) PC13
- (near U15) PC14
- PF10
- PF11
- PF12
- PF13
- PF14
- BOOT0
- EXS00A-MU00525
- (near U15) PC15
- PF15
- (near R15) default : 1-3
- USB_OTG_HS
- (near B1) Reset Button
- SDRAM
- ARDUINO
- CAMERA

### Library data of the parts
B1 = MCD-00171: Switch HW SMD black; Part_Type: Misc; Manufacturer_Part_Number: C-TS-02H-2.5-K-V-T/R BLACK; Manufacturer: JIUBABA; Provided_By: SUBCO
C23 = MCD-00006: as C102 on sheet USB_OTG_HS_externalPHY
C91 C95 = MCD-00563: Capacitor, MLCC, 1.5pF, 50V, NPO, +-0.25pF, 0402, T=0,5mm; Manufacturer_Part_Number: CC0402CRNPO9BN1R5; Manufacturer: YAGEO; Provided_By: SUBCO
C107 C110 = MCD-01727: Capacitor, MLCC, 2.7pF, 50V, NPO, -+0.25pF 0402; Manufacturer_Part_Number: CC0402CRNPO9BN2R7; Manufacturer: YAGEO; Provided_By: SUBCO
R15 R51 R58 = MCD-00053: as R65 on sheet USB_OTG_HS_externalPHY
R62 R63 R74 R78 = MCD-00052: Resistor,0R,0402,5%,1/16W; Manufacturer_Part_Number: RC0402JR-070RL; Manufacturer: YAGEO; Provided_By: SUBCO
R91-R94 R106-R112 = MCD-00455: Resistor,33R,0402,1%,1/16W; Manufacturer_Part_Number: RC0402FR-0733RL; Manufacturer: YAGEO; Provided_By: SUBCO
SB3-SB5 SB31 SB44-SB50 = MCD-00071: as SB40-SB42 on sheet USB_OTG_HS_externalPHY
SW1 = MCD-00566: Mechanical Slide Switches 1K2 BLK ACT GOLD STRT MNT; Part_Type: Misc; Manufacturer_Part_Number: 09.03290.01; Manufacturer: EAO; Provided_By: SUBCO
U1 = MCD-00170: as U26 on sheet USB_OTG_HS_externalPHY
U15 = MCD-02002: STM32H7B3LIH6QU (crypto) - FG: 32H7B3LIH6QU$P2 Cut1.1, TFBGA225 13x13x0.8; Part_Type: IC; Manufacturer: STMICROELECTRONICS; ECCN_US: 5A992C; ECCN_EU: 5A002A4; Provided_By: SUBCO with ST control
X1 = MCD-00091: Crystal 32.768kHz, 6pF, +-20ppm, 50Kohms max, SMD; Manufacturer_Part_Number: NX3215SA 32.768KHz EXS00A-MU00525; Manufacturer: NDK; Part_Type: Crystal_Osc; BMS_Part_Number: 9157034; Provided_By: SUBCO
X4 = MCD-01036: Crystal 24MHz, 6pF, +-20ppm, 80ohms max, SMD; Part_Type: Crystal_Osc; Manufacturer: NDK; BMS_Part_Number: 9157045; Provided_By: SUBCO

## Sheet Arduino.SchDoc: Arduino
size A4; Date: Not used; ApprovedBy: Not used; CheckedBy: Not used; Author: Not used; CompanyName: STMicroelectronics; DrawnBy: Not used; Engineer: Not used; Organization: Not used; Address1: Not used; Address2: Not used; Address3: Not used; Address4: Not used; DocumentNumber: Not used; Revision: Not used; SheetNumber: 12; SheetTotal: 17

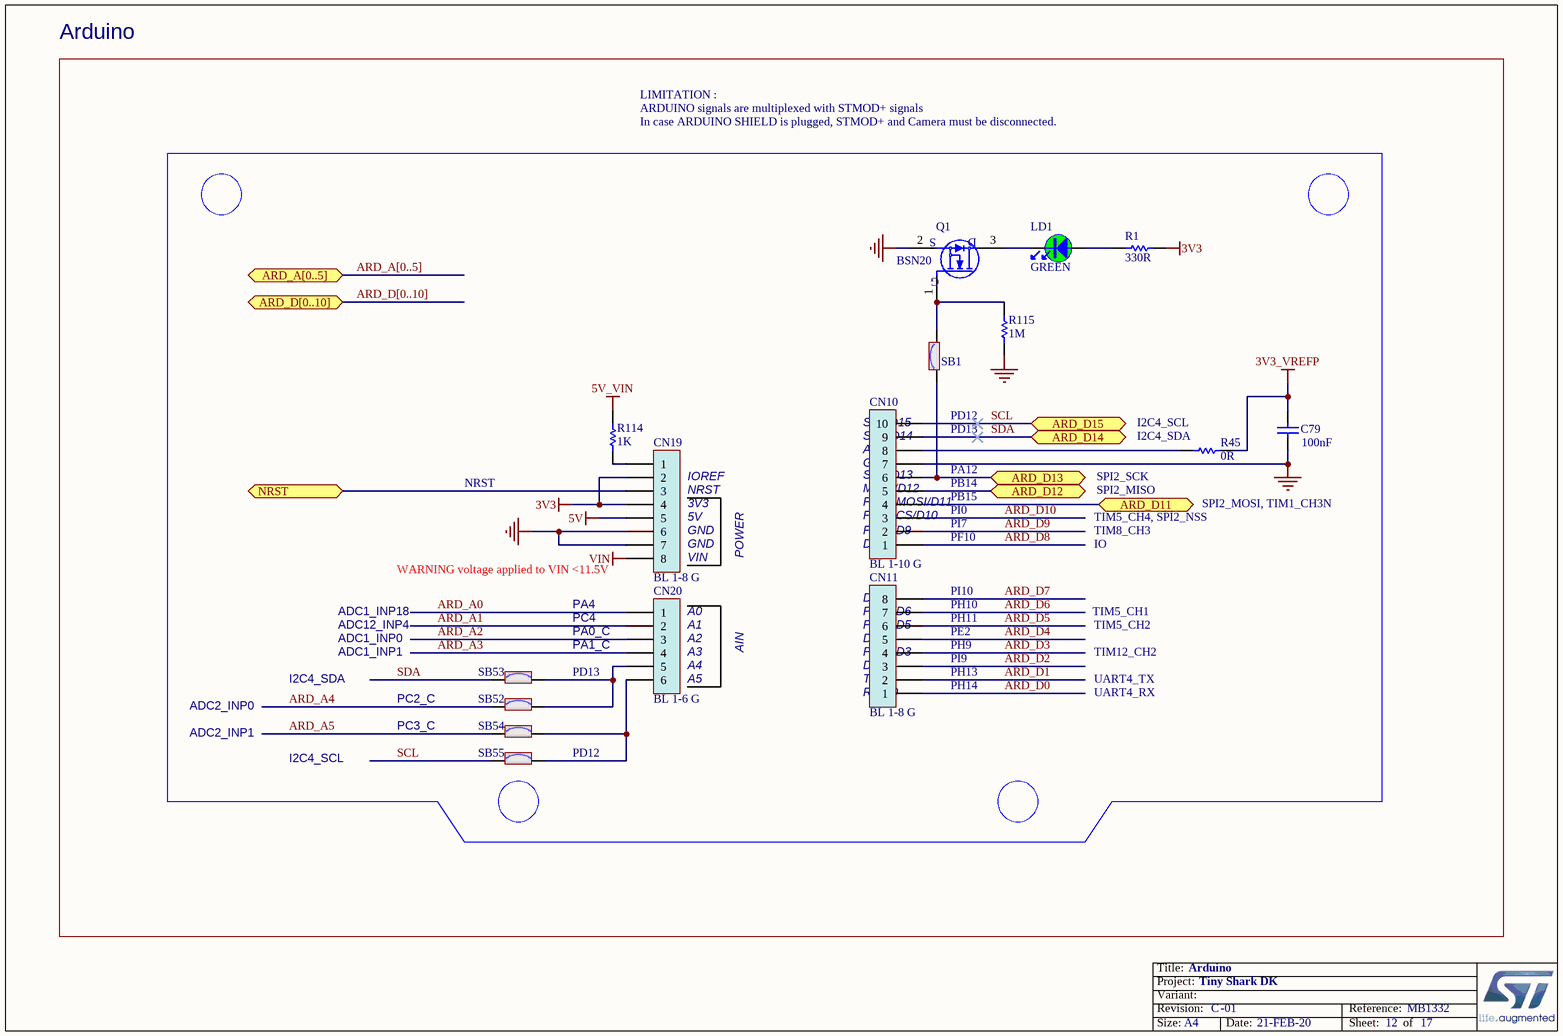
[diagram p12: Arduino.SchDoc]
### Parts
C79  value 100nF  [C0402]  (hidden comment: Capacitor)
CN10  value BL 1-10 G  [CON_FISCHER_BL1-10-G]  (hidden comment: Socket 10x1)
CN11  value BL 1-8 G  [CON_FISCHER_BL1-8-G]  (hidden comment: Socket 8x1)
CN19  value BL 1-8 G  [CON_FISCHER_BL1-8-G]  (hidden comment: Socket 8x1)
CN20  value BL 1-6 G  [CON_FISCHER_BL1-6-G]  (hidden comment: Socket 6x1)
LD1  value GREEN  [LED_0603_OSRAM_LG-Q396-PS-35_GREEN_1A2K_H0P4]  (hidden comment: LED_green)
Q1  BSN20  [MOS_SOT23]
R1  value 330R  [R0402]  (hidden comment: Resistor)
R45  value 0R  [R0402]  (hidden comment: Resistor)
R114  value 1K  [R0402]  (hidden comment: Resistor)
R115  value 1M  [R0402]  (hidden comment: Resistor)
SB1  SB_ON  [SOLDER-BRIDGE_R0603-0R]  (value not drawn)
SB52  SB_ON  [SOLDER-BRIDGE_R0603-0R]  (value not drawn)
SB53  SB_ON  [SOLDER-BRIDGE_R0603-0R]  (value not drawn)
SB54  SB_ON  [SOLDER-BRIDGE_R0603-0R]  (value not drawn)
SB55  SB_ON  [SOLDER-BRIDGE_R0603-0R]  (value not drawn)

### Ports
ARD_A[0..5], ARD_D11, ARD_D12, ARD_D13, ARD_D14, ARD_D15, ARD_D[0..10], NRST (bidir)

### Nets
3V3: CN19.2 CN19.4 R1.2
3V3_VREFP: C79.1 R45.2
5V: CN19.5
5V_VIN: R114.2
GND: C79.2 CN10.7 CN19.6 CN19.7 Q1.2(S) R115.1
VIN: CN19.8
ARD_A0: CN20.1
ARD_A1: CN20.2
ARD_A2: CN20.3
ARD_A3: CN20.4
ARD_A4: SB52.1
ARD_A5: SB54.1
ARD_D0: CN11.1
ARD_D1: CN11.2
ARD_D2: CN11.3
ARD_D3: CN11.4
ARD_D4: CN11.5
ARD_D5: CN11.6
ARD_D6: CN11.7
ARD_D7: CN11.8
ARD_D8: CN10.1
ARD_D9: CN10.2
ARD_D10: CN10.3
ARD_D11: CN10.4 ; port ARD_D11
ARD_D12: CN10.5 ; port ARD_D12
ARD_D13: CN10.6 SB1.1 ; port ARD_D13
SCL: CN10.10 SB55.1 ; port ARD_D15
SDA: CN10.9 SB53.1 ; port ARD_D14
T_NRST: CN19.3 ; port NRST
NetCN10_8: CN10.8 R45.1
NetCN19_1: CN19.1 R114.1
NetCN20_5: CN20.5 SB52.2 SB53.2
NetCN20_6: CN20.6 SB54.2 SB55.2
NetLD1_1: LD1.1 R1.1
NetLD1_2: LD1.2 Q1.3(D)
NetQ1_1: Q1.1(G) R115.2 SB1.2

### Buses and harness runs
bus ARD_A[0..5] = port ARD_A[0..5]
bus ARD_D[0..10] = port ARD_D[0..10]

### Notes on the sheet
- Arduino
- LIMITATION :
  ARDUINO signals are multiplexed with STMOD+ signals
  In case ARDUINO SHIELD is plugged, STMOD+ and Camera must be disconnected.
- (near CN10) SDA/D14
- (near CN10) SCL/D15
- PD12
- PD13
- (near R45) I2C4_SCL
- (near R45) I2C4_SDA
- NRST
- (near CN19) IOREF
- (near CN19) NRST
- (near CN19) 3V3
- (near CN19) 5V
- (near CN10) PWM/CS/D10
- (near CN10) SCK/D13
- (near CN10) MISO/D12
- (near CN10) PWM/MOSI/D11
- (near CN10) AVDD
- (near CN10) GND
- PI0
- PA12
- PB14
- PB15
- TIM5_CH4, SPI2_NSS
- (near R45) SPI2_SCK
- SPI2_MISO
- SPI2_MOSI, TIM1_CH3N
- WARNING voltage applied to VIN <11.5V
- (near CN19) GND
- (near CN19) VIN
- POWER
- (near CN10) D8
- (near CN10) PWM/D9
- PF10
- PI7
- TIM8_CH3
- IO
- ADC1_INP0
- ADC1_INP1
- ADC1_INP18
- ADC12_INP4
- PA1_C
- PA0_C
- PC4
- PA4
- (near CN20) A0
- (near CN20) A1
- (near CN20) A2
- (near CN20) A3
- AIN
- (near CN11) D4
- (near CN11) PWM/D3
- (near CN11) PWM/D5
- (near CN11) PWM/D6
- (near CN11) D7
- PH9
- PH10
- PE2
- PI10
- PH11
- TIM5_CH1
- TIM5_CH2
- TIM12_CH2
- ADC2_INP0
- I2C4_SDA
- PC2_C
- (near CN20) A4
- (near CN20) A5
- (near CN11) RX/D0
- (near CN11) TX/D1
- (near CN11) D2
- PI9
- PH14
- PH13
- UART4_TX
- UART4_RX
- ADC2_INP1
- I2C4_SCL
- PC3_C

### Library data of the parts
C79 = MCD-00006: as C102 on sheet USB_OTG_HS_externalPHY
CN10 = MCD-00024: Socket, 10x1, 2.54mm, VR, TH, Height 8mm/3.3mm; Part_Type: Connector; Manufacturer: FISCHER ELECTRONIK; Alternate_Manufacturer_Part_Number: 218110S1610; Alternate_Manufacturer: JIUBABA; Provided_By: SUBCO
CN11 CN19 = MCD-00025: Socket, 8x1, 2.54mm, VR, TH, Height 8mm/3.3mm; Part_Type: Connector; Manufacturer: FISCHER ELECTRONIK; Alternate_Manufacturer_Part_Number: 218108S1610; Alternate_Manufacturer: JIUBABA; Provided_By: SUBCO
CN20 = MCD-00026: Socket, 6x1, 2.54mm, VR, TH, Height 8mm/3.3mm; Part_Type: Connector; Manufacturer: FISCHER ELECTRONIK; Alternate_Manufacturer_Part_Number: 218106S1610; Alternate_Manufacturer: JIUBABA; Provided_By: SUBCO
LD1 = MCD-00588: as LD6 on sheet USB_OTG_HS_externalPHY
Q1 = MCD-00151: N-channel enhancement mode field-effect transistor; Part_Type: IC; Manufacturer: NXP; Provided_By: SUBCO
R1 = MCD-00062: Resistor,330R,0402,1%,1/16W; Manufacturer_Part_Number: RC0402FR-07330RL; Manufacturer: YAGEO; Provided_By: SUBCO
R45 = MCD-00052: as R62 on sheet MCU
R114 = MCD-00061: Resistor,1K,0402,1%,1/16W; Manufacturer_Part_Number: RC0402FR-071KL; Manufacturer: YAGEO; Provided_By: SUBCO
R115 = MCD-00182: Resistor,1M,0402,1%,1/16W; Manufacturer_Part_Number: RC0402FR-071ML; Manufacturer: YAGEO; Provided_By: SUBCO
SB1 SB52-SB55 = MCD-00071: as SB40-SB42 on sheet USB_OTG_HS_externalPHY

## Sheet JTAG.SchDoc: JTAG
size A4; Date: Not used; ApprovedBy: Not used; CheckedBy: Not used; Author: Not used; CompanyName: STMicroelectronics; DrawnBy: Not used; Engineer: Not used; Organization: Not used; Address1: Not used; Address2: Not used; Address3: Not used; Address4: Not used; DocumentNumber: Not used; Revision: Not used; SheetNumber: 16; SheetTotal: 17

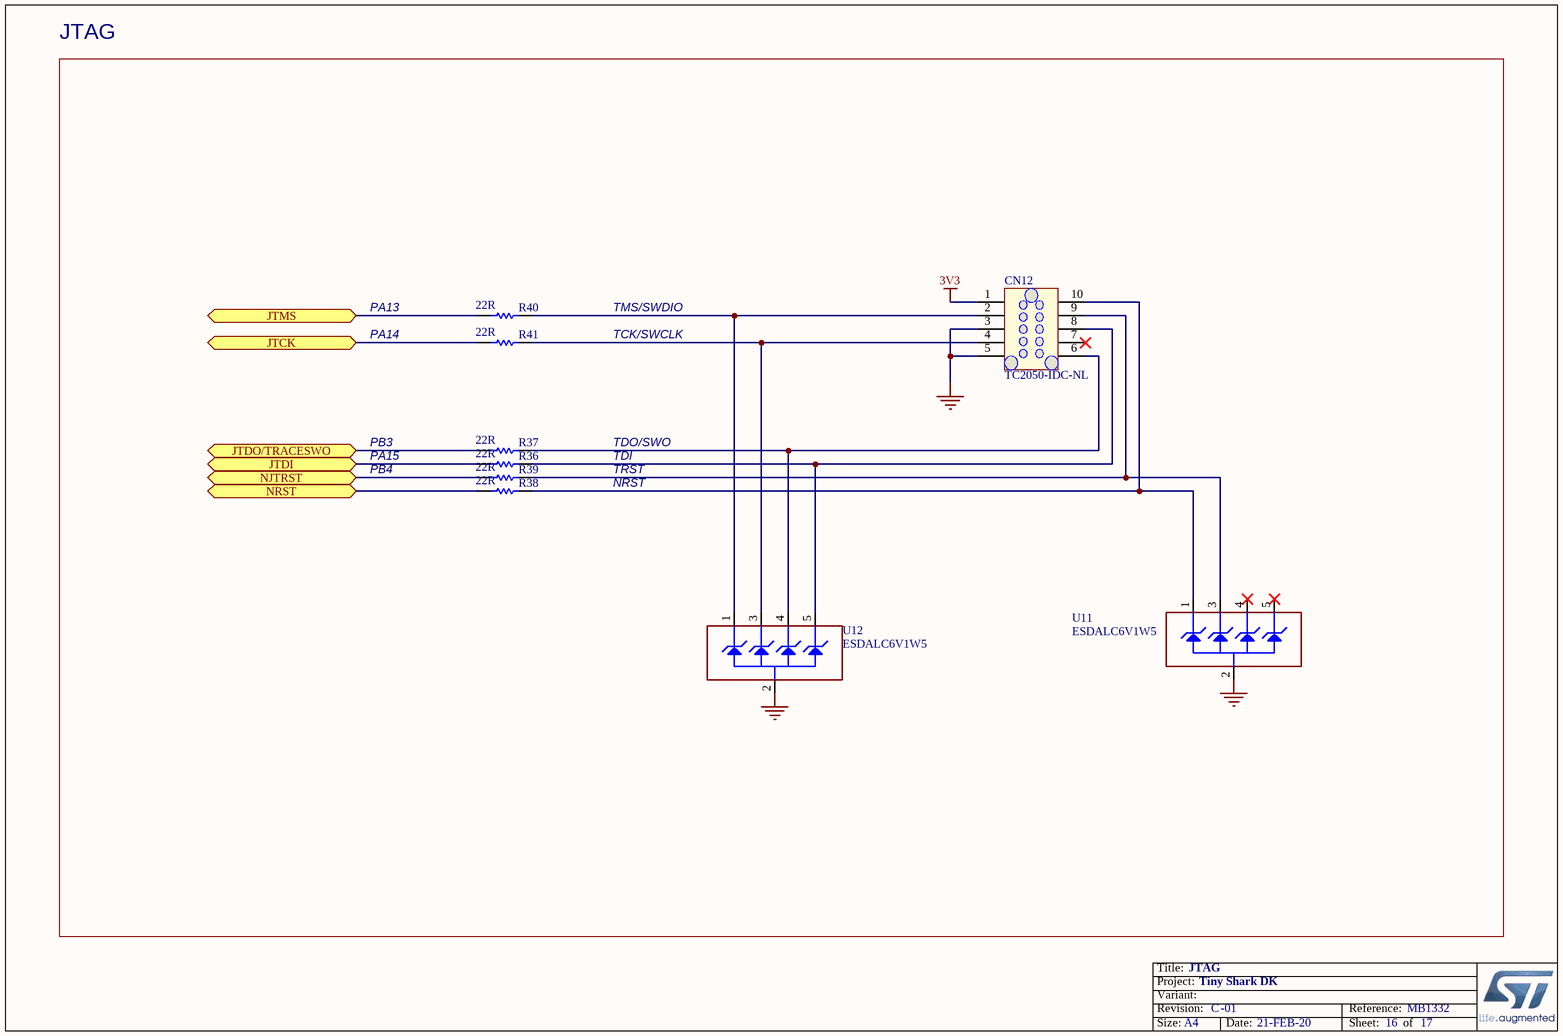
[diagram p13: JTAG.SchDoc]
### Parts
CN12  value TC2050-IDC-NL  [CON_TAG-C_TC2050-IDC-NL]  (hidden comment: Tag-10-C)
R36  value 22R  [R0603]  (hidden comment: Resistor)
R37  value 22R  [R0603]  (hidden comment: Resistor)
R38  value 22R  [R0603]  (hidden comment: Resistor)
R39  value 22R  [R0603]  (hidden comment: Resistor)
R40  value 22R  [R0603]  (hidden comment: Resistor)
R41  value 22R  [R0603]  (hidden comment: Resistor)
U11  ESDALC6V1W5  [ESD_SOT323-5L]
U12  ESDALC6V1W5  [ESD_SOT323-5L]

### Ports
JTCK, JTDI, JTDO/TRACESWO, JTMS, NJTRST, NRST

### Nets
3V3: CN12.1
GND: CN12.3 CN12.5 U11.2(GND) U12.2(GND)
JTDI: R36.2 ; port JTDI
NJTRST: R39.2 ; port NJTRST
T_NRST: R38.2 ; port NRST
T_SWCLK: R41.2 ; port JTCK
T_SWDIO: R40.2 ; port JTMS
T_SWO: R37.2 ; port JTDO/TRACESWO
NetCN12_2: CN12.2 R40.1 U12.1(IO1)
NetCN12_4: CN12.4 R41.1 U12.3(IO2)
NetCN12_6: CN12.6 R37.1 U12.4(IO3)
NetCN12_8: CN12.8 R36.1 U12.5(IO4)
NetCN12_9: CN12.9 R39.1 U11.3(IO2)
NetCN12_10: CN12.10 R38.1 U11.1(IO1)

Not connected (* = marked no-connect by the designer): CN12 7*; U11 4(IO3)* 5(IO4)*

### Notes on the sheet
- JTAG
- PA13
- TMS/SWDIO
- PA14
- TCK/SWCLK
- PB3
- TDO/SWO
- PA15
- PB4
- TDI
- TRST
- NRST

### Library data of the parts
CN12 = MCD-00031: Tag_Connector Header, 10x2, No legs; Manufacturer_Part_Number: TC2050-IDC-NL-FP; Manufacturer: TAG-CONNECT LLC; Provided_By: SUBCO
R36-R41 = MCD-00066: Resistor,22R,0603,1%,1/10W; Manufacturer_Part_Number: RC0603FR-0722RL; Manufacturer: YAGEO; Provided_By: SUBCO
U11 U12 = MCD-00136: Dual Transil array for ESD protection; Part_Type: Diode; Manufacturer: STMICROELECTRONICS; BMS_Part_Number: 9151112; Provided_By: SUBCO with ST control

## Sheet STLink_V3E_SWD.SchDoc: ST-LINK-V3E SWD
size A3; Date: Not used; ApprovedBy: Not used; CheckedBy: Not used; Author: Not used; CompanyName: STMicroelectronics; DrawnBy: Not used; Engineer: Not used; Organization: Not used; Address1: Not used; Address2: Not used; Address3: Not used; Address4: Not used; DocumentNumber: Not used; Revision: Not used; SheetNumber: 17; SheetTotal: 17

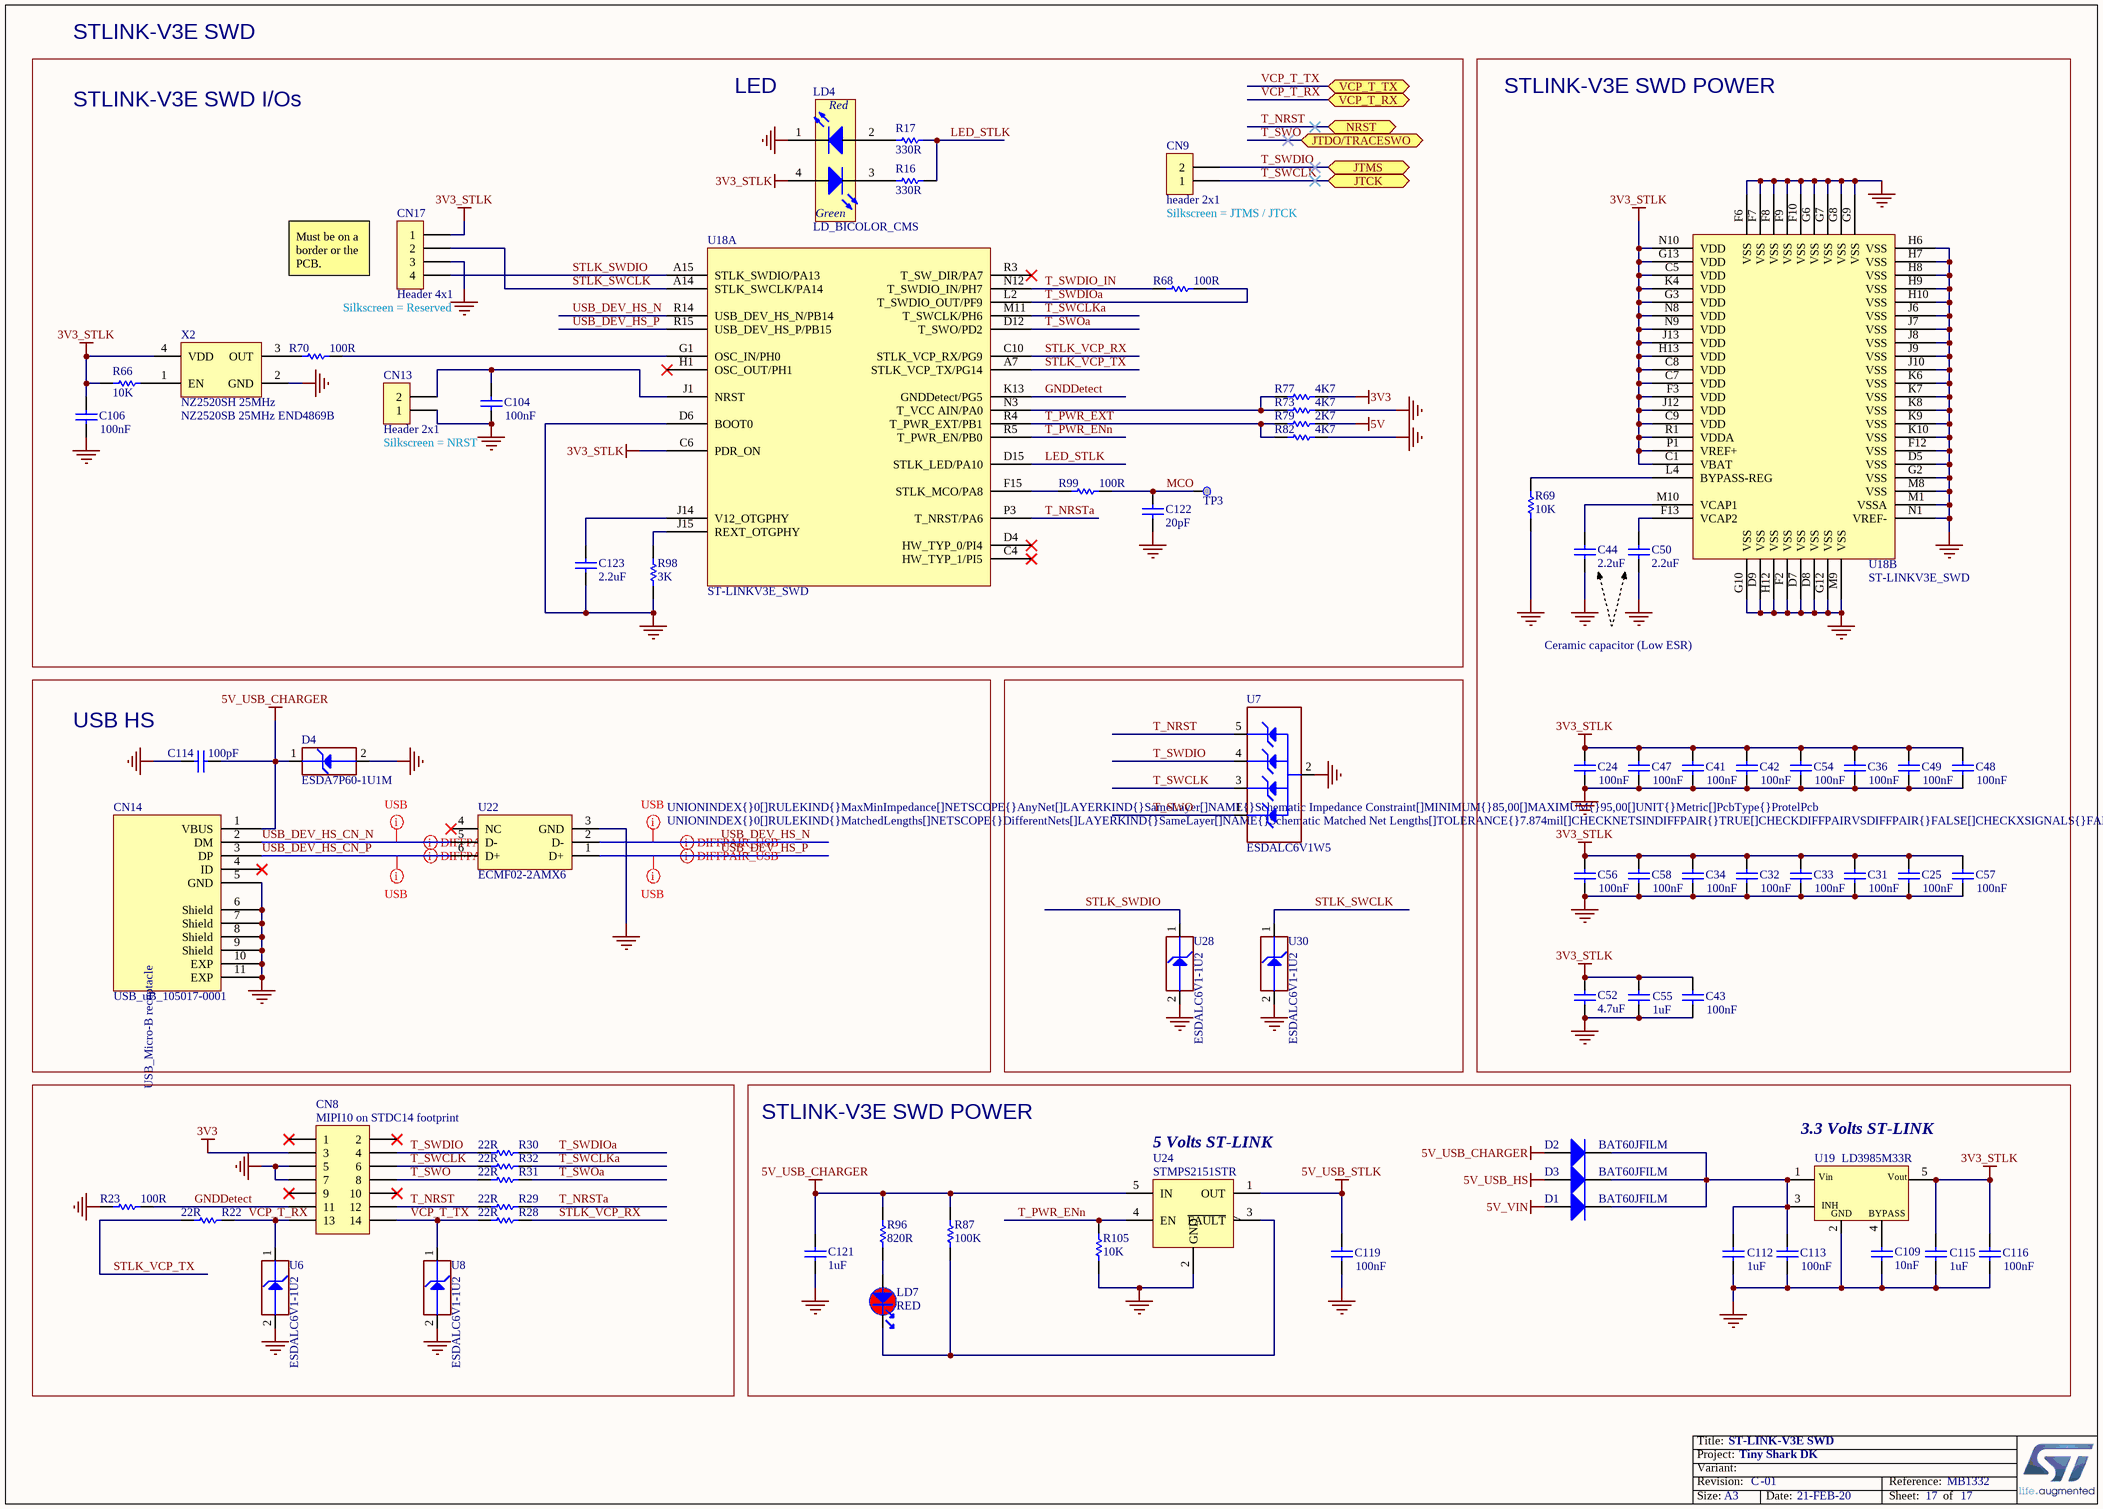
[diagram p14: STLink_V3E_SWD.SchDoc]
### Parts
C24  value 100nF  [C0402]  (hidden comment: Capacitor)
C25  value 100nF  [C0402]  (hidden comment: Capacitor)
C31  value 100nF  [C0402]  (hidden comment: Capacitor)
C32  value 100nF  [C0402]  (hidden comment: Capacitor)
C33  value 100nF  [C0402]  (hidden comment: Capacitor)
C34  value 100nF  [C0402]  (hidden comment: Capacitor)
C36  value 100nF  [C0402]  (hidden comment: Capacitor)
C41  value 100nF  [C0402]  (hidden comment: Capacitor)
C42  value 100nF  [C0402]  (hidden comment: Capacitor)
C43  value 100nF  [C0402]  (hidden comment: Capacitor)
C44  value 2.2uF  [C0603]  (hidden comment: Capacitor)
C47  value 100nF  [C0402]  (hidden comment: Capacitor)
C48  value 100nF  [C0402]  (hidden comment: Capacitor)
C49  value 100nF  [C0402]  (hidden comment: Capacitor)
C50  value 2.2uF  [C0603]  (hidden comment: Capacitor)
C52  value 4.7uF  [C0603]  (hidden comment: Capacitor)
C54  value 100nF  [C0402]  (hidden comment: Capacitor)
C55  value 1uF  [C0603]  (hidden comment: Capacitor)
C56  value 100nF  [C0402]  (hidden comment: Capacitor)
C57  value 100nF  [C0402]  (hidden comment: Capacitor)
C58  value 100nF  [C0402]  (hidden comment: Capacitor)
C104  value 100nF  [C0402]  (hidden comment: Capacitor)
C106  value 100nF  [C0402]  (hidden comment: Capacitor)
C109  value 10nF  [C0402]  (hidden comment: Capacitor)
C112  value 1uF  [C0603]  (hidden comment: Capacitor)
C113  value 100nF  [C0402]  (hidden comment: Capacitor)
C114  value 100pF  [C0402]  (hidden comment: Capacitor)
C115  value 1uF  [C0603]  (hidden comment: Capacitor)
C116  value 100nF  [C0402]  (hidden comment: Capacitor)
C119  value 100nF  [C0402]  (hidden comment: Capacitor)
C121  value 1uF  [C0603]  (hidden comment: Capacitor)
C122  value 20pF  [C0402]  (hidden comment: Capacitor)
C123  value 2.2uF  [C0603]  (hidden comment: Capacitor)
CN8  value MIPI10 on STDC14 footprint  [CON_STDC14_Receiver_MEDIUM_WITH_MIPI10_3D]  (hidden comment: Header 7x2)
CN9  Header 2x1  [CON_988-JIUBABA_PHFS25-11-02-G0B115-T-1]
CN13  Header 2x1  [CON_SAMTEC_TSW-102-07-G-S]
CN14  value USB_uB_105017-0001  [CON_USBMICROB_MOLEX_105017-0001_H2P90]  (hidden comment: USB_uB_105017.0001)
CN17  Header 4x1  [CON_SAMTEC_TSW-104-07-G-S]
D1  BAT60JFILM  [DIO_SOD323]
D2  BAT60JFILM  [DIO_SOD323]
D3  BAT60JFILM  [DIO_SOD323]
D4  value ESDA7P60-1U1M  [ESD_QFN2_1P6X1_P125]  (hidden comment: ESD-TRANSIL)
LD4  LD_BICOLOR_CMS  [LED_BI-GR_HSMF-A201-A00J1]
LD7  value RED  [LED_0603_VISHAY_VLMS1300-GS08_RED_1A2K_H0P8]  (hidden comment: LED_red)
R16  value 330R  [R0603]  (hidden comment: Resistor)
R17  value 330R  [R0603]  (hidden comment: Resistor)
R22  value 22R  [R0603]  (hidden comment: Resistor)
R23  value 100R  [R0402]  (hidden comment: Resistor)
R28  value 22R  [R0603]  (hidden comment: Resistor)
R29  value 22R  [R0603]  (hidden comment: Resistor)
R30  value 22R  [R0603]  (hidden comment: Resistor)
R31  value 22R  [R0603]  (hidden comment: Resistor)
R32  value 22R  [R0603]  (hidden comment: Resistor)
R66  value 10K  [R0402]  (hidden comment: Resistor)
R68  value 100R  [R0402]  (hidden comment: Resistor)
R69  value 10K  [R0402]  (hidden comment: Resistor)
R70  value 100R  [R0402]  (hidden comment: Resistor)
R73  value 4K7  [R0402]  (hidden comment: Resistor)
R77  value 4K7  [R0402]  (hidden comment: Resistor)
R79  value 2K7  [R0402]  (hidden comment: Resistor)
R82  value 4K7  [R0402]  (hidden comment: Resistor)
R87  value 100K  [R0402]  (hidden comment: Resistor)
R96  value 820R  [R0402]  (hidden comment: Resistor)
R98  value 3K  [R0402]  (hidden comment: Resistor)
R99  value 100R  [R0402]  (hidden comment: Resistor)
R105  value 10K  [R0402]  (hidden comment: Resistor)
TP3  Test Point  [TP_SMD_1MM]  (value not drawn)  (no BOM)
U6  value ESDALC6V1-1U2  [ESD_ST0201]  (hidden comment: ESD-TRANSIL)
U7  ESDALC6V1W5  [ESD_SOT323-5L]
U8  value ESDALC6V1-1U2  [ESD_ST0201]  (hidden comment: ESD-TRANSIL)
U18  ST-LINKV3E_SWD  [ICC_UFBGA201_176+25_10X10_P065]  (parts A,B of 2)
U19  LD3985M33R  [REG_SOT23-5L]
U22  ECMF02-2AMX6  [ESD_QFN-6L_1P7X1P5_P050]
U24  STMPS2151STR  [MOS_SOT23-5L]
U28  value ESDALC6V1-1U2  [ESD_ST0201]  (hidden comment: ESD-TRANSIL)
U30  value ESDALC6V1-1U2  [ESD_ST0201]  (hidden comment: ESD-TRANSIL)
X2  value NZ2520SH 25MHz  [OSC_NDK_NZ2520SB_4P]  (hidden comment: OSCILLATOR_4_PINS)

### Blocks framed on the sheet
STLINK-V3E SWD POWER: C24 C25 C31-C34 C36 C41-C44 C47-C50 C52 C54-C58 R69 U18
USB HS: C114 CN14 D4 U22
STLINK-V3E SWD POWER: C109 C112 C113 C115 C116 C119 C121 D1-D3 LD7 R87 R96 R105 U19 U24

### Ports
JTCK, JTDO/TRACESWO, JTMS, NRST, VCP_T_RX, VCP_T_TX

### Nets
3V3: CN8.3 R77.2
3V3_STLK: C24.1 C25.1 C31.1 C32.1 C33.1 C34.1 C36.1 C41.1 C42.1 C43.1 C47.1 C48.1 C49.1 C52.2 C54.1 C55.2 C56.1 C57.1 C58.1 C106.1 C115.2 C116.1 CN17.1 LD4.4(YellowGreen_anode) R66.1 U18.C1(VBAT) U18.C5(VDD) U18.C6(PDR_ON) U18.C7(VDD) U18.C8(VDD) U18.C9(VDD) U18.F3(VDD) U18.G3(VDD) U18.G13(VDD) U18.H13(VDD) U18.J12(VDD) U18.J13(VDD) U18.K4(VDD) U18.N8(VDD) U18.N9(VDD) U18.N10(VDD) U18.P1(VREF+) U18.R1(VDDA) U19.5(Vout) X2.4(VDD)
5V: R79.1
5V_USB_CHARGER: C114.2 C121.2 CN14.1(VBUS) D2.1(A) D4.1(IO1) R87.1 R96.2 U24.5(IN)
5V_USB_HS: D3.1(A)
5V_USB_STLK: C119.1 U24.1(OUT)
5V_VIN: D1.1(A)
GND: C24.2 C25.2 C31.2 C32.2 C33.2 C34.2 C36.2 C41.2 C42.2 C43.2 C44.1 C47.2 C48.2 C49.2 C50.1 C52.1 C54.2 C55.1 C56.2 C57.2 C58.2 C104.2 C106.2 C109.1 C112.1 C113.2 C114.1 C115.1 C116.2 C119.2 C121.1 C122.1 C123.1 CN8.5 CN8.7 CN13.1 CN14.5(GND) CN14.6(Shield) CN14.7(Shield) CN14.8(Shield) CN14.9(Shield) CN14.10(EXP) CN14.11(EXP) CN17.3 D4.2(GND) LD4.1(RED_cathode) R23.1 R69.1 R73.2 R82.1 R98.1 R105.2 U6.2(GND) U7.2(GND) U8.2(GND) U18.D5(VSS) U18.D6(BOOT0) U18.D7(VSS) U18.D8(VSS) U18.D9(VSS) U18.F2(VSS) U18.F6(VSS) U18.F7(VSS) U18.F8(VSS) U18.F9(VSS) U18.F10(VSS) U18.F12(VSS) U18.G2(VSS) U18.G6(VSS) U18.G7(VSS) U18.G8(VSS) U18.G9(VSS) U18.G10(VSS) U18.G12(VSS) U18.H6(VSS) U18.H7(VSS) U18.H8(VSS) U18.H9(VSS) U18.H10(VSS) U18.H12(VSS) U18.J6(VSS) U18.J7(VSS) U18.J8(VSS) U18.J9(VSS) U18.J10(VSS) U18.K6(VSS) U18.K7(VSS) U18.K8(VSS) U18.K9(VSS) U18.K10(VSS) U18.M1(VSSA) U18.M8(VSS) U18.M9(VSS) U18.N1(VREF-) U19.2(GND) U22.3(GND) U24.2(GND) U28.2(GND) U30.2(GND) X2.2(GND)
GNDDetect: CN8.11 R23.2 U18.K13(GNDDetect/PG5)
LED_STLK: R16.2 R17.2 U18.D15(STLK_LED/PA10)
MCO: C122.2 R99.2 TP3.1
STLK_SWCLK: CN17.2 U18.A14(STLK_SWCLK/PA14) U30.1(IO1)
STLK_SWDIO: CN17.4 U18.A15(STLK_SWDIO/PA13) U28.1(IO1)
STLK_VCP_RX: R28.1 U18.C10(STLK_VCP_RX/PG9)
STLK_VCP_TX: R22.2 U18.A7(STLK_VCP_TX/PG14)
T_NRST: CN8.12 R29.2 U7.5(IO4) ; port NRST
T_NRSTa: R29.1 U18.P3(T_NRST/PA6)
T_PWR_ENn: R105.1 U18.R5(T_PWR_EN/PB0) U24.4(EN)
T_PWR_EXT: R79.2 R82.2 U18.R4(T_PWR_EXT/PB1)
T_SWCLK: CN8.6 CN9.1 R32.2 U7.3(IO2) ; port JTCK
T_SWCLKa: R32.1 U18.M11(T_SWCLK/PH6)
T_SWDIO: CN8.4 CN9.2 R30.2 U7.4(IO3) ; port JTMS
T_SWDIO_IN: R68.1 U18.N12(T_SWDIO_IN/PH7)
T_SWDIOa: R30.1 R68.2 U18.L2(T_SWDIO_OUT/PF9)
T_SWO: CN8.8 R31.2 U7.1(IO1) ; port JTDO/TRACESWO
T_SWOa: R31.1 U18.D12(T_SWO/PD2)
USB_DEV_HS_CN_N: CN14.2(DM) U22.5(D-)
USB_DEV_HS_CN_P: CN14.3(DP) U22.6(D+)
USB_DEV_HS_N: U18.R14(USB_DEV_HS_N/PB14) U22.2(D-)
USB_DEV_HS_P: U18.R15(USB_DEV_HS_P/PB15) U22.1(D+)
VCP_T_RX: CN8.13 R22.1 U6.1(IO1) ; port VCP_T_RX
VCP_T_TX: CN8.14 R28.2 U8.1(IO1) ; port VCP_T_TX
NetC44_2: C44.2 U18.M10(VCAP1)
NetC50_2: C50.2 U18.F13(VCAP2)
NetC104_1: C104.1 CN13.2 U18.J1(NRST)
NetC109_2: C109.2 U19.4(BYPASS)
NetC112_2: C112.2 C113.1 D1.2(K) D2.2(K) D3.2(K) U19.1(Vin) U19.3(CE)
NetC123_2: C123.2 U18.J14(V12_OTGPHY)
NetLD4_2: LD4.2(Red_anode) R17.1
NetLD4_3: LD4.3(YellowGreen_cathode) R16.1
NetLD7_1: LD7.1 R96.1
NetLD7_2: LD7.2 R87.2 U24.3(~{FAULT})
NetR66_2: R66.2 X2.1(EN)
NetR69_2: R69.2 U18.L4(BYPASS-REG)
NetR70_1: R70.1 X2.3(OUT)
NetR70_2: R70.2 U18.G1(OSC_IN/PH0)
NetR73_1: R73.1 R77.1 U18.N3(T_VCC_AIN/PA0)
NetR98_2: R98.2 U18.J15(REXT_OTGPHY)
NetR99_1: R99.1 U18.F15(STLK_MCO/PA8)

Not connected (* = marked no-connect by the designer): CN8 1* 2* 9* 10*; CN14 4(ID)*; U18 C4(HW_TYP_1/PI5)* D4(HW_TYP_0/PI4)* H1(OSC_OUT/PH1)* R3(T_SW_DIR/PA7)*; U22 4(NC)*

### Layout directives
differential pair; rule Impedance Constraint [Min = 85.00    Max = 95.00    ]: USB_DEV_HS_CN_N, USB_DEV_HS_CN_P, USB_DEV_HS_N, USB_DEV_HS_P
rule Undefined; rule Matched Net Lengths [Tolerance = 0.2mm]; rule Impedance Constraint [Min = 85.00    Max = 95.00    ]: USB_DEV_HS_CN_N, USB_DEV_HS_CN_P, USB_DEV_HS_N, USB_DEV_HS_P

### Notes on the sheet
- STLINK-V3E SWD
- STLINK-V3E SWD I/Os
- LED
- (near CN9) Silkscreen = JTMS / JTCK
- Must be on a border or the PCB.
- Silkscreen = Reserved
- (near X2) NZ2520SB 25MHz END4869B
- Silkscreen = NRST
- Ceramic capacitor (Low ESR)
- (near U24) 5 Volts ST-LINK
- (near U19) 3.3 Volts ST-LINK

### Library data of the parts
C24 C25 C31-C34 C36 C41-C43 C47-C49 C54 C56-C58 C104 C106 C113 C116 C119 = MCD-00006: as C102 on sheet USB_OTG_HS_externalPHY
C44 C50 C123 = MCD-00012: as C120 on sheet USB_OTG_HS_externalPHY
C52 = MCD-00009: Capacitor, MLCC, 4.7uF, 16V, X5R, 10%, 0603, T=0.8mm; Manufacturer_Part_Number: CC0603KRX5R7BB475; Manufacturer: YAGEO; Provided_By: SUBCO
C55 C112 C115 C121 = MCD-00010: Capacitor, MLCC, 1uF, 16V, X5R, 10%, 0603, T=0,8mm; Manufacturer_Part_Number: CC0603KRX5R7BB105; Manufacturer: YAGEO; Provided_By: SUBCO
C109 = MCD-00011: Capacitor, MLCC, 10nF, 16V, X7R, 10%, 0402, T=0.5mm; Manufacturer_Part_Number: CC0402KRX7R7BB103; Manufacturer: YAGEO; Provided_By: SUBCO
C114 = MCD-00205: Capacitor, MLCC, 100pF, 50V, NPO, 5%, 0402, T=0,5mm; Manufacturer_Part_Number: CC0402JRNPO9BN101; Manufacturer: YAGEO; Provided_By: SUBCO
C122 = MCD-00016: Capacitor, MLCC, 20pF, 50V, NPO, 5%, 0402, T=0,5mm; Manufacturer_Part_Number: CC0402JRNPO9BN200; Manufacturer: YAGEO; Provided_By: SUBCO
CN8 = MCD-01226: Header 5x2, 1.27mm, Dual row, Straight, Surface mount, vertical male connector. 3.05mm lead. Mates with FFSD connector. Footprint compatible with FTSH-107-01-L-DV,-K,-A,-P,-ES (STDC14 MEDIUM); Manufacturer_Part_Number: FTSH-105-01-L-DV-K; Manufacturer: SAMTEC; Provided_By: SUBCO
CN9 = MCD-00314: Header, 2x1, 2.54mm, VR, TH, Height 6mm/3mm; Part_Type: Connector; Manufacturer_Part_Number: PHFS25-11-02-G0B115-T-1; Manufacturer: JIUBABA; Provided_By: SUBCO
CN13 = MCD-00032: Header, 2x1, 2,54mm, VR, TH, Height 5.84mm/2.54mm; Part_Type: Connector; Manufacturer_Part_Number: TSW-102-07-x-S; Manufacturer: SAMTEC; Alternate_Manufacturer_Part_Number: 313102S111116; Alternate_Manufacturer: JIUBABA; Provided_By: SUBCO
CN14 = MCD-00028: USB-MICRO-B, 0.65mm, RA, SMT, Bottom Mount,; Manufacturer_Part_Number: 1050170001; Manufacturer: MOLEX; Part_Type: Connector; Provided_By: SUBCO
CN17 = MCD-00029: Header, 4x1, 2,54mm, VR, TH, Height 5.84mm/2.54mm; Manufacturer_Part_Number: TSW-104-07-x-S; Manufacturer: SAMTEC; Part_Type: Connector; Provided_By: SUBCO
D1-D3 = MCD-00034: Manufacturer: STMICROELECTRONICS; Part_Type: Diode; BMS_Part_Number: 9151097; Provided_By: SUBCO with ST control
D4 = MCD-00251: as U21 on sheet USB_OTG_HS_externalPHY
LD4 = MCD-00051: LED Bicolor; Part_Type: Display; Manufacturer_Part_Number: HSMF-A201-A00J1; Manufacturer: AVAGO TECHNOLOGIES; Alternate_Manufacturer_Part_Number: LE-RGW35280; Alternate_Manufacturer: EVERLUCK; Provided_By: SUBCO
LD7 = MCD-00587: LED Red, 0603 SMD, 2V Forward Voltage; Part_Type: Display; Manufacturer_Part_Number: VLMS1300-GS08; Manufacturer: VISHAY; Alternate_Manufacturer_Part_Number: LS Q976-NR-1; Alternate_Manufacturer: OSRAM OPTO SEMICONDUCTORS; Provided_By: SUBCO
R16 R17 = MCD-00197: as R80 on sheet USB_OTG_HS_externalPHY
R22 R28-R32 = MCD-00066: as R36 on sheet JTAG
R23 R68 R70 R99 = MCD-00119: Resistor,100R,0402,1%,1/16W; Manufacturer_Part_Number: RC0402FR-07100RL; Manufacturer: YAGEO; Provided_By: SUBCO
R66 R69 R105 = MCD-00053: as R65 on sheet USB_OTG_HS_externalPHY
R73 R77 R82 = MCD-00065: as R75 on sheet USB_OTG_HS_externalPHY
R79 = MCD-00055: Resistor,2K7,0402,1%,1/16W; Manufacturer_Part_Number: RC0402FR-072K7L; Manufacturer: YAGEO; Provided_By: SUBCO
R87 = MCD-00059: as R76 on sheet USB_OTG_HS_externalPHY
R96 = MCD-00527: Resistor,820R,0402,1%,1/16W; Manufacturer_Part_Number: RC0402FR-07820RL; Manufacturer: YAGEO; Provided_By: SUBCO
R98 = MCD-00185: Resistor,3K,0402,1%,1/16W; Manufacturer_Part_Number: RC0402FR-073KL; Manufacturer: YAGEO; Provided_By: SUBCO
TP3 = MCD-00074: Test Point 1mm; Part_Type: Mechanical
U6 U8 U28 U30 = MCD-00170: as U26 on sheet USB_OTG_HS_externalPHY
U7 = MCD-00136: as U11 on sheet JTAG
U18 = MCD-00596: STM32F723IEK  (STM32F7) BGA176; Part_Type: IC; Manufacturer_Part_Number: STM32F723IEK6; Manufacturer: STMICROELECTRONICS; BMS_Part_Number: 9175300; Provided_By: SUBCO with ST control
U19 = MCD-00086: Ultra low drop-low noise BiCMOS voltage, regulators low ESR capacitors compatible; Manufacturer: STMICROELECTRONICS; Part_Type: IC; BMS_Part_Number: 9176161; Provided_By: SUBCO with ST control
U22 = MCD-00649: as U23 on sheet USB_OTG_HS_externalPHY
U24 = MCD-00159: 500mA, Enhanced single channel power switches with active high enable pin; Part_Type: IC; Manufacturer: STMICROELECTRONICS; Alternate_Manufacturer_Part_Number: TPS2051C; Alternate_Manufacturer: TEXAS INSTRUMENTS; BMS_Part_Number: 9159009; Provided_By: SUBCO with ST control
X2 = MCD-00597: Oscillator 25Mhz, +-50ppm, Vcc:3.3V typ, square wave: [0.1Vcc;0.9Vcc], Enable pin, SMD; Manufacturer_Part_Number: NZ2520SH 25MHz END4869C; Manufacturer: NDK; Alternate_Manufacturer_Part_Number: NZ2520SB 25MHz END4869B; Part_Type: Crystal_Osc; BMS_Part_Number: 9157050; Provided_By: SUBCO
